VERSION 5.8 ;
BUSBITCHARS "[]" ;
DIVIDERCHAR "/" ;
UNITS
    DATABASE MICRONS 1000 ;
END UNITS

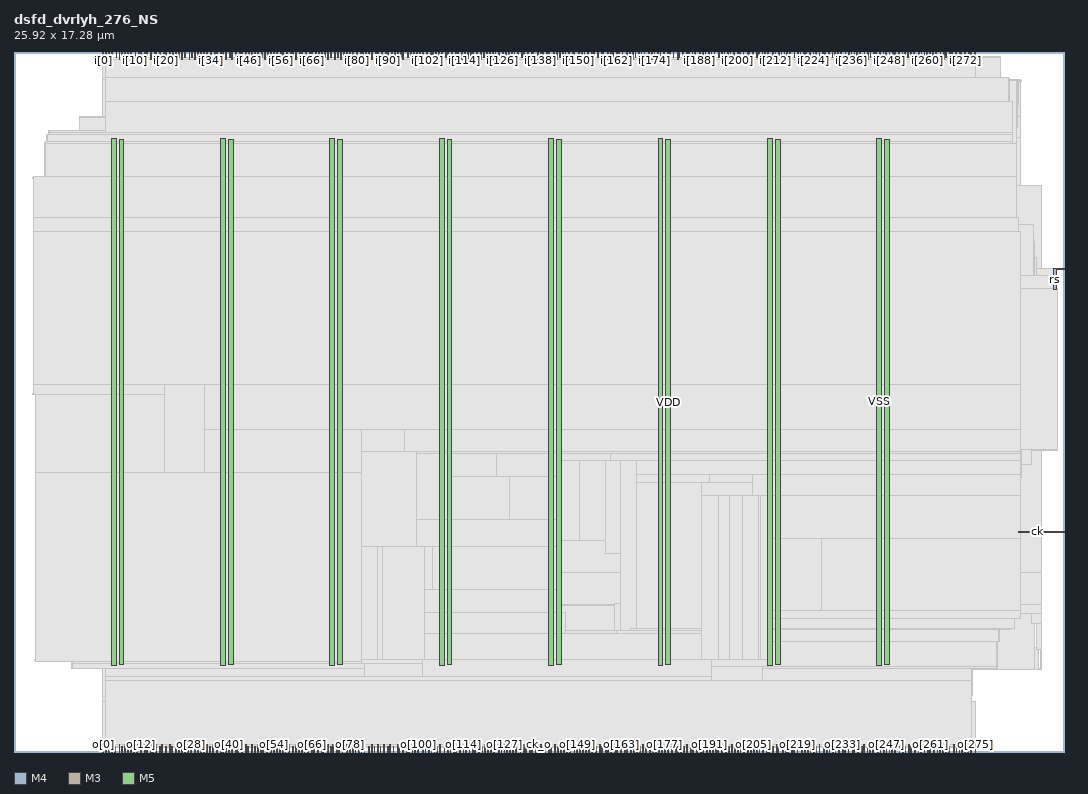
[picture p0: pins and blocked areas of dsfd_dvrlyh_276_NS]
MACRO dsfd_dvrlyh_276_NS
  FOREIGN dsfd_dvrlyh_276_NS 0 0 ;
  CLASS BLOCK ;
  SIZE 25.92 BY 17.28 ;
  PIN ck
    DIRECTION INPUT ;
    USE SIGNAL ;
    PORT
      LAYER M4 ;
        RECT  25.728 5.424 25.92 5.448 ;
    END
    PORT
      LAYER M4 ;
        RECT  24.803 5.424 25.74 5.448 ;
    END
  END ck
  PIN ck_o
    DIRECTION OUTPUT ;
    USE SIGNAL ;
    PORT
      LAYER M3 ;
        RECT  12.96 0 12.978 0.144 ;
    END
  END ck_o
  PIN i[0]
    DIRECTION INPUT ;
    USE SIGNAL ;
    PORT
      LAYER M3 ;
        RECT  2.196 17.136 2.214 17.28 ;
    END
  END i[0]
  PIN i[100]
    DIRECTION INPUT ;
    USE SIGNAL ;
    PORT
      LAYER M3 ;
        RECT  10.008 17.136 10.026 17.28 ;
    END
  END i[100]
  PIN i[101]
    DIRECTION INPUT ;
    USE SIGNAL ;
    PORT
      LAYER M5 ;
        RECT  10.08 17.088 10.104 17.28 ;
    END
  END i[101]
  PIN i[102]
    DIRECTION INPUT ;
    USE SIGNAL ;
    PORT
      LAYER M3 ;
        RECT  10.188 17.136 10.206 17.28 ;
    END
  END i[102]
  PIN i[103]
    DIRECTION INPUT ;
    USE SIGNAL ;
    PORT
      LAYER M5 ;
        RECT  10.272 17.088 10.296 17.28 ;
    END
  END i[103]
  PIN i[104]
    DIRECTION INPUT ;
    USE SIGNAL ;
    PORT
      LAYER M3 ;
        RECT  10.332 17.136 10.35 17.28 ;
    END
  END i[104]
  PIN i[105]
    DIRECTION INPUT ;
    USE SIGNAL ;
    PORT
      LAYER M5 ;
        RECT  10.416 17.088 10.44 17.28 ;
    END
  END i[105]
  PIN i[106]
    DIRECTION INPUT ;
    USE SIGNAL ;
    PORT
      LAYER M3 ;
        RECT  10.476 17.136 10.494 17.28 ;
    END
  END i[106]
  PIN i[107]
    DIRECTION INPUT ;
    USE SIGNAL ;
    PORT
      LAYER M5 ;
        RECT  10.56 17.088 10.584 17.28 ;
    END
  END i[107]
  PIN i[108]
    DIRECTION INPUT ;
    USE SIGNAL ;
    PORT
      LAYER M3 ;
        RECT  10.656 17.136 10.674 17.28 ;
    END
  END i[108]
  PIN i[109]
    DIRECTION INPUT ;
    USE SIGNAL ;
    PORT
      LAYER M5 ;
        RECT  10.704 17.088 10.728 17.28 ;
    END
  END i[109]
  PIN i[10]
    DIRECTION INPUT ;
    USE SIGNAL ;
    PORT
      LAYER M3 ;
        RECT  2.988 17.136 3.006 17.28 ;
    END
  END i[10]
  PIN i[110]
    DIRECTION INPUT ;
    USE SIGNAL ;
    PORT
      LAYER M3 ;
        RECT  10.8 17.136 10.818 17.28 ;
    END
  END i[110]
  PIN i[111]
    DIRECTION INPUT ;
    USE SIGNAL ;
    PORT
      LAYER M5 ;
        RECT  10.896 17.088 10.92 17.28 ;
    END
  END i[111]
  PIN i[112]
    DIRECTION INPUT ;
    USE SIGNAL ;
    PORT
      LAYER M3 ;
        RECT  10.944 17.136 10.962 17.28 ;
    END
  END i[112]
  PIN i[113]
    DIRECTION INPUT ;
    USE SIGNAL ;
    PORT
      LAYER M5 ;
        RECT  11.04 17.088 11.064 17.28 ;
    END
  END i[113]
  PIN i[114]
    DIRECTION INPUT ;
    USE SIGNAL ;
    PORT
      LAYER M3 ;
        RECT  11.124 17.136 11.142 17.28 ;
    END
  END i[114]
  PIN i[115]
    DIRECTION INPUT ;
    USE SIGNAL ;
    PORT
      LAYER M5 ;
        RECT  11.184 17.088 11.208 17.28 ;
    END
  END i[115]
  PIN i[116]
    DIRECTION INPUT ;
    USE SIGNAL ;
    PORT
      LAYER M3 ;
        RECT  11.268 17.136 11.286 17.28 ;
    END
  END i[116]
  PIN i[117]
    DIRECTION INPUT ;
    USE SIGNAL ;
    PORT
      LAYER M5 ;
        RECT  11.328 17.088 11.352 17.28 ;
    END
  END i[117]
  PIN i[118]
    DIRECTION INPUT ;
    USE SIGNAL ;
    PORT
      LAYER M3 ;
        RECT  11.412 17.136 11.43 17.28 ;
    END
  END i[118]
  PIN i[119]
    DIRECTION INPUT ;
    USE SIGNAL ;
    PORT
      LAYER M5 ;
        RECT  11.52 17.088 11.544 17.28 ;
    END
  END i[119]
  PIN i[11]
    DIRECTION INPUT ;
    USE SIGNAL ;
    PORT
      LAYER M5 ;
        RECT  3.072 17.088 3.096 17.28 ;
    END
  END i[11]
  PIN i[120]
    DIRECTION INPUT ;
    USE SIGNAL ;
    PORT
      LAYER M3 ;
        RECT  11.592 17.136 11.61 17.28 ;
    END
  END i[120]
  PIN i[121]
    DIRECTION INPUT ;
    USE SIGNAL ;
    PORT
      LAYER M5 ;
        RECT  11.664 17.088 11.688 17.28 ;
    END
  END i[121]
  PIN i[122]
    DIRECTION INPUT ;
    USE SIGNAL ;
    PORT
      LAYER M3 ;
        RECT  11.736 17.136 11.754 17.28 ;
    END
  END i[122]
  PIN i[123]
    DIRECTION INPUT ;
    USE SIGNAL ;
    PORT
      LAYER M5 ;
        RECT  11.808 17.088 11.832 17.28 ;
    END
  END i[123]
  PIN i[124]
    DIRECTION INPUT ;
    USE SIGNAL ;
    PORT
      LAYER M3 ;
        RECT  11.88 17.136 11.898 17.28 ;
    END
  END i[124]
  PIN i[125]
    DIRECTION INPUT ;
    USE SIGNAL ;
    PORT
      LAYER M5 ;
        RECT  11.952 17.088 11.976 17.28 ;
    END
  END i[125]
  PIN i[126]
    DIRECTION INPUT ;
    USE SIGNAL ;
    PORT
      LAYER M3 ;
        RECT  12.06 17.136 12.078 17.28 ;
    END
  END i[126]
  PIN i[127]
    DIRECTION INPUT ;
    USE SIGNAL ;
    PORT
      LAYER M5 ;
        RECT  12.144 17.088 12.168 17.28 ;
    END
  END i[127]
  PIN i[128]
    DIRECTION INPUT ;
    USE SIGNAL ;
    PORT
      LAYER M3 ;
        RECT  12.204 17.136 12.222 17.28 ;
    END
  END i[128]
  PIN i[129]
    DIRECTION INPUT ;
    USE SIGNAL ;
    PORT
      LAYER M5 ;
        RECT  12.288 17.088 12.312 17.28 ;
    END
  END i[129]
  PIN i[12]
    DIRECTION INPUT ;
    USE SIGNAL ;
    PORT
      LAYER M3 ;
        RECT  3.132 17.136 3.15 17.28 ;
    END
  END i[12]
  PIN i[130]
    DIRECTION INPUT ;
    USE SIGNAL ;
    PORT
      LAYER M3 ;
        RECT  12.348 17.136 12.366 17.28 ;
    END
  END i[130]
  PIN i[131]
    DIRECTION INPUT ;
    USE SIGNAL ;
    PORT
      LAYER M5 ;
        RECT  12.432 17.088 12.456 17.28 ;
    END
  END i[131]
  PIN i[132]
    DIRECTION INPUT ;
    USE SIGNAL ;
    PORT
      LAYER M3 ;
        RECT  12.528 17.136 12.546 17.28 ;
    END
  END i[132]
  PIN i[133]
    DIRECTION INPUT ;
    USE SIGNAL ;
    PORT
      LAYER M5 ;
        RECT  12.576 17.088 12.6 17.28 ;
    END
  END i[133]
  PIN i[134]
    DIRECTION INPUT ;
    USE SIGNAL ;
    PORT
      LAYER M3 ;
        RECT  12.672 17.136 12.69 17.28 ;
    END
  END i[134]
  PIN i[135]
    DIRECTION INPUT ;
    USE SIGNAL ;
    PORT
      LAYER M5 ;
        RECT  12.768 17.088 12.792 17.28 ;
    END
  END i[135]
  PIN i[136]
    DIRECTION INPUT ;
    USE SIGNAL ;
    PORT
      LAYER M3 ;
        RECT  12.816 17.136 12.834 17.28 ;
    END
  END i[136]
  PIN i[137]
    DIRECTION INPUT ;
    USE SIGNAL ;
    PORT
      LAYER M5 ;
        RECT  12.912 17.088 12.936 17.28 ;
    END
  END i[137]
  PIN i[138]
    DIRECTION INPUT ;
    USE SIGNAL ;
    PORT
      LAYER M3 ;
        RECT  12.996 17.136 13.014 17.28 ;
    END
  END i[138]
  PIN i[139]
    DIRECTION INPUT ;
    USE SIGNAL ;
    PORT
      LAYER M5 ;
        RECT  13.056 17.088 13.08 17.28 ;
    END
  END i[139]
  PIN i[13]
    DIRECTION INPUT ;
    USE SIGNAL ;
    PORT
      LAYER M5 ;
        RECT  3.216 17.088 3.24 17.28 ;
    END
  END i[13]
  PIN i[140]
    DIRECTION INPUT ;
    USE SIGNAL ;
    PORT
      LAYER M3 ;
        RECT  13.14 17.136 13.158 17.28 ;
    END
  END i[140]
  PIN i[141]
    DIRECTION INPUT ;
    USE SIGNAL ;
    PORT
      LAYER M5 ;
        RECT  13.2 17.088 13.224 17.28 ;
    END
  END i[141]
  PIN i[142]
    DIRECTION INPUT ;
    USE SIGNAL ;
    PORT
      LAYER M3 ;
        RECT  13.32 17.136 13.338 17.28 ;
    END
  END i[142]
  PIN i[143]
    DIRECTION INPUT ;
    USE SIGNAL ;
    PORT
      LAYER M5 ;
        RECT  13.392 17.088 13.416 17.28 ;
    END
  END i[143]
  PIN i[144]
    DIRECTION INPUT ;
    USE SIGNAL ;
    PORT
      LAYER M3 ;
        RECT  13.464 17.136 13.482 17.28 ;
    END
  END i[144]
  PIN i[145]
    DIRECTION INPUT ;
    USE SIGNAL ;
    PORT
      LAYER M5 ;
        RECT  13.536 17.088 13.56 17.28 ;
    END
  END i[145]
  PIN i[146]
    DIRECTION INPUT ;
    USE SIGNAL ;
    PORT
      LAYER M3 ;
        RECT  13.608 17.136 13.626 17.28 ;
    END
  END i[146]
  PIN i[147]
    DIRECTION INPUT ;
    USE SIGNAL ;
    PORT
      LAYER M5 ;
        RECT  13.68 17.088 13.704 17.28 ;
    END
  END i[147]
  PIN i[148]
    DIRECTION INPUT ;
    USE SIGNAL ;
    PORT
      LAYER M3 ;
        RECT  13.788 17.136 13.806 17.28 ;
    END
  END i[148]
  PIN i[149]
    DIRECTION INPUT ;
    USE SIGNAL ;
    PORT
      LAYER M5 ;
        RECT  13.824 17.088 13.848 17.28 ;
    END
  END i[149]
  PIN i[14]
    DIRECTION INPUT ;
    USE SIGNAL ;
    PORT
      LAYER M3 ;
        RECT  3.276 17.136 3.294 17.28 ;
    END
  END i[14]
  PIN i[150]
    DIRECTION INPUT ;
    USE SIGNAL ;
    PORT
      LAYER M3 ;
        RECT  13.932 17.136 13.95 17.28 ;
    END
  END i[150]
  PIN i[151]
    DIRECTION INPUT ;
    USE SIGNAL ;
    PORT
      LAYER M5 ;
        RECT  14.016 17.088 14.04 17.28 ;
    END
  END i[151]
  PIN i[152]
    DIRECTION INPUT ;
    USE SIGNAL ;
    PORT
      LAYER M3 ;
        RECT  14.076 17.136 14.094 17.28 ;
    END
  END i[152]
  PIN i[153]
    DIRECTION INPUT ;
    USE SIGNAL ;
    PORT
      LAYER M5 ;
        RECT  14.16 17.088 14.184 17.28 ;
    END
  END i[153]
  PIN i[154]
    DIRECTION INPUT ;
    USE SIGNAL ;
    PORT
      LAYER M3 ;
        RECT  14.256 17.136 14.274 17.28 ;
    END
  END i[154]
  PIN i[155]
    DIRECTION INPUT ;
    USE SIGNAL ;
    PORT
      LAYER M5 ;
        RECT  14.304 17.088 14.328 17.28 ;
    END
  END i[155]
  PIN i[156]
    DIRECTION INPUT ;
    USE SIGNAL ;
    PORT
      LAYER M3 ;
        RECT  14.4 17.136 14.418 17.28 ;
    END
  END i[156]
  PIN i[157]
    DIRECTION INPUT ;
    USE SIGNAL ;
    PORT
      LAYER M5 ;
        RECT  14.496 17.088 14.52 17.28 ;
    END
  END i[157]
  PIN i[158]
    DIRECTION INPUT ;
    USE SIGNAL ;
    PORT
      LAYER M3 ;
        RECT  14.544 17.136 14.562 17.28 ;
    END
  END i[158]
  PIN i[159]
    DIRECTION INPUT ;
    USE SIGNAL ;
    PORT
      LAYER M5 ;
        RECT  14.64 17.088 14.664 17.28 ;
    END
  END i[159]
  PIN i[15]
    DIRECTION INPUT ;
    USE SIGNAL ;
    PORT
      LAYER M5 ;
        RECT  3.36 17.088 3.384 17.28 ;
    END
  END i[15]
  PIN i[160]
    DIRECTION INPUT ;
    USE SIGNAL ;
    PORT
      LAYER M3 ;
        RECT  14.724 17.136 14.742 17.28 ;
    END
  END i[160]
  PIN i[161]
    DIRECTION INPUT ;
    USE SIGNAL ;
    PORT
      LAYER M5 ;
        RECT  14.784 17.088 14.808 17.28 ;
    END
  END i[161]
  PIN i[162]
    DIRECTION INPUT ;
    USE SIGNAL ;
    PORT
      LAYER M3 ;
        RECT  14.868 17.136 14.886 17.28 ;
    END
  END i[162]
  PIN i[163]
    DIRECTION INPUT ;
    USE SIGNAL ;
    PORT
      LAYER M5 ;
        RECT  14.928 17.088 14.952 17.28 ;
    END
  END i[163]
  PIN i[164]
    DIRECTION INPUT ;
    USE SIGNAL ;
    PORT
      LAYER M3 ;
        RECT  15.012 17.136 15.03 17.28 ;
    END
  END i[164]
  PIN i[165]
    DIRECTION INPUT ;
    USE SIGNAL ;
    PORT
      LAYER M5 ;
        RECT  15.12 17.088 15.144 17.28 ;
    END
  END i[165]
  PIN i[166]
    DIRECTION INPUT ;
    USE SIGNAL ;
    PORT
      LAYER M3 ;
        RECT  15.192 17.136 15.21 17.28 ;
    END
  END i[166]
  PIN i[167]
    DIRECTION INPUT ;
    USE SIGNAL ;
    PORT
      LAYER M5 ;
        RECT  15.264 17.088 15.288 17.28 ;
    END
  END i[167]
  PIN i[168]
    DIRECTION INPUT ;
    USE SIGNAL ;
    PORT
      LAYER M3 ;
        RECT  15.336 17.136 15.354 17.28 ;
    END
  END i[168]
  PIN i[169]
    DIRECTION INPUT ;
    USE SIGNAL ;
    PORT
      LAYER M5 ;
        RECT  15.408 17.088 15.432 17.28 ;
    END
  END i[169]
  PIN i[16]
    DIRECTION INPUT ;
    USE SIGNAL ;
    PORT
      LAYER M3 ;
        RECT  3.456 17.136 3.474 17.28 ;
    END
  END i[16]
  PIN i[170]
    DIRECTION INPUT ;
    USE SIGNAL ;
    PORT
      LAYER M3 ;
        RECT  15.48 17.136 15.498 17.28 ;
    END
  END i[170]
  PIN i[171]
    DIRECTION INPUT ;
    USE SIGNAL ;
    PORT
      LAYER M5 ;
        RECT  15.552 17.088 15.576 17.28 ;
    END
  END i[171]
  PIN i[172]
    DIRECTION INPUT ;
    USE SIGNAL ;
    PORT
      LAYER M3 ;
        RECT  15.66 17.136 15.678 17.28 ;
    END
  END i[172]
  PIN i[173]
    DIRECTION INPUT ;
    USE SIGNAL ;
    PORT
      LAYER M5 ;
        RECT  15.744 17.088 15.768 17.28 ;
    END
  END i[173]
  PIN i[174]
    DIRECTION INPUT ;
    USE SIGNAL ;
    PORT
      LAYER M3 ;
        RECT  15.804 17.136 15.822 17.28 ;
    END
  END i[174]
  PIN i[175]
    DIRECTION INPUT ;
    USE SIGNAL ;
    PORT
      LAYER M5 ;
        RECT  15.888 17.088 15.912 17.28 ;
    END
  END i[175]
  PIN i[176]
    DIRECTION INPUT ;
    USE SIGNAL ;
    PORT
      LAYER M3 ;
        RECT  15.948 17.136 15.966 17.28 ;
    END
  END i[176]
  PIN i[177]
    DIRECTION INPUT ;
    USE SIGNAL ;
    PORT
      LAYER M5 ;
        RECT  16.032 17.088 16.056 17.28 ;
    END
  END i[177]
  PIN i[178]
    DIRECTION INPUT ;
    USE SIGNAL ;
    PORT
      LAYER M3 ;
        RECT  16.128 17.136 16.146 17.28 ;
    END
  END i[178]
  PIN i[179]
    DIRECTION INPUT ;
    USE SIGNAL ;
    PORT
      LAYER M5 ;
        RECT  16.176 17.088 16.2 17.28 ;
    END
  END i[179]
  PIN i[17]
    DIRECTION INPUT ;
    USE SIGNAL ;
    PORT
      LAYER M5 ;
        RECT  3.504 17.088 3.528 17.28 ;
    END
  END i[17]
  PIN i[180]
    DIRECTION INPUT ;
    USE SIGNAL ;
    PORT
      LAYER M3 ;
        RECT  16.272 17.136 16.29 17.28 ;
    END
  END i[180]
  PIN i[181]
    DIRECTION INPUT ;
    USE SIGNAL ;
    PORT
      LAYER M5 ;
        RECT  16.368 17.088 16.392 17.28 ;
    END
  END i[181]
  PIN i[182]
    DIRECTION INPUT ;
    USE SIGNAL ;
    PORT
      LAYER M3 ;
        RECT  16.416 17.136 16.434 17.28 ;
    END
  END i[182]
  PIN i[183]
    DIRECTION INPUT ;
    USE SIGNAL ;
    PORT
      LAYER M5 ;
        RECT  16.512 17.088 16.536 17.28 ;
    END
  END i[183]
  PIN i[184]
    DIRECTION INPUT ;
    USE SIGNAL ;
    PORT
      LAYER M3 ;
        RECT  16.596 17.136 16.614 17.28 ;
    END
  END i[184]
  PIN i[185]
    DIRECTION INPUT ;
    USE SIGNAL ;
    PORT
      LAYER M5 ;
        RECT  16.656 17.088 16.68 17.28 ;
    END
  END i[185]
  PIN i[186]
    DIRECTION INPUT ;
    USE SIGNAL ;
    PORT
      LAYER M3 ;
        RECT  16.74 17.136 16.758 17.28 ;
    END
  END i[186]
  PIN i[187]
    DIRECTION INPUT ;
    USE SIGNAL ;
    PORT
      LAYER M5 ;
        RECT  16.8 17.088 16.824 17.28 ;
    END
  END i[187]
  PIN i[188]
    DIRECTION INPUT ;
    USE SIGNAL ;
    PORT
      LAYER M3 ;
        RECT  16.92 17.136 16.938 17.28 ;
    END
  END i[188]
  PIN i[189]
    DIRECTION INPUT ;
    USE SIGNAL ;
    PORT
      LAYER M5 ;
        RECT  16.992 17.088 17.016 17.28 ;
    END
  END i[189]
  PIN i[18]
    DIRECTION INPUT ;
    USE SIGNAL ;
    PORT
      LAYER M3 ;
        RECT  3.6 17.136 3.618 17.28 ;
    END
  END i[18]
  PIN i[190]
    DIRECTION INPUT ;
    USE SIGNAL ;
    PORT
      LAYER M3 ;
        RECT  17.064 17.136 17.082 17.28 ;
    END
  END i[190]
  PIN i[191]
    DIRECTION INPUT ;
    USE SIGNAL ;
    PORT
      LAYER M5 ;
        RECT  17.136 17.088 17.16 17.28 ;
    END
  END i[191]
  PIN i[192]
    DIRECTION INPUT ;
    USE SIGNAL ;
    PORT
      LAYER M3 ;
        RECT  17.208 17.136 17.226 17.28 ;
    END
  END i[192]
  PIN i[193]
    DIRECTION INPUT ;
    USE SIGNAL ;
    PORT
      LAYER M5 ;
        RECT  17.28 17.088 17.304 17.28 ;
    END
  END i[193]
  PIN i[194]
    DIRECTION INPUT ;
    USE SIGNAL ;
    PORT
      LAYER M3 ;
        RECT  17.388 17.136 17.406 17.28 ;
    END
  END i[194]
  PIN i[195]
    DIRECTION INPUT ;
    USE SIGNAL ;
    PORT
      LAYER M5 ;
        RECT  17.472 17.088 17.496 17.28 ;
    END
  END i[195]
  PIN i[196]
    DIRECTION INPUT ;
    USE SIGNAL ;
    PORT
      LAYER M3 ;
        RECT  17.532 17.136 17.55 17.28 ;
    END
  END i[196]
  PIN i[197]
    DIRECTION INPUT ;
    USE SIGNAL ;
    PORT
      LAYER M5 ;
        RECT  17.616 17.088 17.64 17.28 ;
    END
  END i[197]
  PIN i[198]
    DIRECTION INPUT ;
    USE SIGNAL ;
    PORT
      LAYER M3 ;
        RECT  17.676 17.136 17.694 17.28 ;
    END
  END i[198]
  PIN i[199]
    DIRECTION INPUT ;
    USE SIGNAL ;
    PORT
      LAYER M5 ;
        RECT  17.76 17.088 17.784 17.28 ;
    END
  END i[199]
  PIN i[19]
    DIRECTION INPUT ;
    USE SIGNAL ;
    PORT
      LAYER M5 ;
        RECT  3.696 17.088 3.72 17.28 ;
    END
  END i[19]
  PIN i[1]
    DIRECTION INPUT ;
    USE SIGNAL ;
    PORT
      LAYER M5 ;
        RECT  2.256 17.088 2.28 17.28 ;
    END
  END i[1]
  PIN i[200]
    DIRECTION INPUT ;
    USE SIGNAL ;
    PORT
      LAYER M3 ;
        RECT  17.856 17.136 17.874 17.28 ;
    END
  END i[200]
  PIN i[201]
    DIRECTION INPUT ;
    USE SIGNAL ;
    PORT
      LAYER M5 ;
        RECT  17.904 17.088 17.928 17.28 ;
    END
  END i[201]
  PIN i[202]
    DIRECTION INPUT ;
    USE SIGNAL ;
    PORT
      LAYER M3 ;
        RECT  18 17.136 18.018 17.28 ;
    END
  END i[202]
  PIN i[203]
    DIRECTION INPUT ;
    USE SIGNAL ;
    PORT
      LAYER M5 ;
        RECT  18.096 17.088 18.12 17.28 ;
    END
  END i[203]
  PIN i[204]
    DIRECTION INPUT ;
    USE SIGNAL ;
    PORT
      LAYER M3 ;
        RECT  18.144 17.136 18.162 17.28 ;
    END
  END i[204]
  PIN i[205]
    DIRECTION INPUT ;
    USE SIGNAL ;
    PORT
      LAYER M5 ;
        RECT  18.24 17.088 18.264 17.28 ;
    END
  END i[205]
  PIN i[206]
    DIRECTION INPUT ;
    USE SIGNAL ;
    PORT
      LAYER M3 ;
        RECT  18.324 17.136 18.342 17.28 ;
    END
  END i[206]
  PIN i[207]
    DIRECTION INPUT ;
    USE SIGNAL ;
    PORT
      LAYER M5 ;
        RECT  18.384 17.088 18.408 17.28 ;
    END
  END i[207]
  PIN i[208]
    DIRECTION INPUT ;
    USE SIGNAL ;
    PORT
      LAYER M3 ;
        RECT  18.468 17.136 18.486 17.28 ;
    END
  END i[208]
  PIN i[209]
    DIRECTION INPUT ;
    USE SIGNAL ;
    PORT
      LAYER M5 ;
        RECT  18.528 17.088 18.552 17.28 ;
    END
  END i[209]
  PIN i[20]
    DIRECTION INPUT ;
    USE SIGNAL ;
    PORT
      LAYER M3 ;
        RECT  3.744 17.136 3.762 17.28 ;
    END
  END i[20]
  PIN i[210]
    DIRECTION INPUT ;
    USE SIGNAL ;
    PORT
      LAYER M3 ;
        RECT  18.612 17.136 18.63 17.28 ;
    END
  END i[210]
  PIN i[211]
    DIRECTION INPUT ;
    USE SIGNAL ;
    PORT
      LAYER M5 ;
        RECT  18.72 17.088 18.744 17.28 ;
    END
  END i[211]
  PIN i[212]
    DIRECTION INPUT ;
    USE SIGNAL ;
    PORT
      LAYER M3 ;
        RECT  18.792 17.136 18.81 17.28 ;
    END
  END i[212]
  PIN i[213]
    DIRECTION INPUT ;
    USE SIGNAL ;
    PORT
      LAYER M5 ;
        RECT  18.864 17.088 18.888 17.28 ;
    END
  END i[213]
  PIN i[214]
    DIRECTION INPUT ;
    USE SIGNAL ;
    PORT
      LAYER M3 ;
        RECT  18.936 17.136 18.954 17.28 ;
    END
  END i[214]
  PIN i[215]
    DIRECTION INPUT ;
    USE SIGNAL ;
    PORT
      LAYER M5 ;
        RECT  19.008 17.088 19.032 17.28 ;
    END
  END i[215]
  PIN i[216]
    DIRECTION INPUT ;
    USE SIGNAL ;
    PORT
      LAYER M3 ;
        RECT  19.08 17.136 19.098 17.28 ;
    END
  END i[216]
  PIN i[217]
    DIRECTION INPUT ;
    USE SIGNAL ;
    PORT
      LAYER M5 ;
        RECT  19.152 17.088 19.176 17.28 ;
    END
  END i[217]
  PIN i[218]
    DIRECTION INPUT ;
    USE SIGNAL ;
    PORT
      LAYER M3 ;
        RECT  19.26 17.136 19.278 17.28 ;
    END
  END i[218]
  PIN i[219]
    DIRECTION INPUT ;
    USE SIGNAL ;
    PORT
      LAYER M5 ;
        RECT  19.344 17.088 19.368 17.28 ;
    END
  END i[219]
  PIN i[21]
    DIRECTION INPUT ;
    USE SIGNAL ;
    PORT
      LAYER M5 ;
        RECT  3.84 17.088 3.864 17.28 ;
    END
  END i[21]
  PIN i[220]
    DIRECTION INPUT ;
    USE SIGNAL ;
    PORT
      LAYER M3 ;
        RECT  19.404 17.136 19.422 17.28 ;
    END
  END i[220]
  PIN i[221]
    DIRECTION INPUT ;
    USE SIGNAL ;
    PORT
      LAYER M5 ;
        RECT  19.488 17.088 19.512 17.28 ;
    END
  END i[221]
  PIN i[222]
    DIRECTION INPUT ;
    USE SIGNAL ;
    PORT
      LAYER M3 ;
        RECT  19.548 17.136 19.566 17.28 ;
    END
  END i[222]
  PIN i[223]
    DIRECTION INPUT ;
    USE SIGNAL ;
    PORT
      LAYER M5 ;
        RECT  19.632 17.088 19.656 17.28 ;
    END
  END i[223]
  PIN i[224]
    DIRECTION INPUT ;
    USE SIGNAL ;
    PORT
      LAYER M3 ;
        RECT  19.728 17.136 19.746 17.28 ;
    END
  END i[224]
  PIN i[225]
    DIRECTION INPUT ;
    USE SIGNAL ;
    PORT
      LAYER M5 ;
        RECT  19.776 17.088 19.8 17.28 ;
    END
  END i[225]
  PIN i[226]
    DIRECTION INPUT ;
    USE SIGNAL ;
    PORT
      LAYER M3 ;
        RECT  19.872 17.136 19.89 17.28 ;
    END
  END i[226]
  PIN i[227]
    DIRECTION INPUT ;
    USE SIGNAL ;
    PORT
      LAYER M5 ;
        RECT  19.968 17.088 19.992 17.28 ;
    END
  END i[227]
  PIN i[228]
    DIRECTION INPUT ;
    USE SIGNAL ;
    PORT
      LAYER M3 ;
        RECT  20.016 17.136 20.034 17.28 ;
    END
  END i[228]
  PIN i[229]
    DIRECTION INPUT ;
    USE SIGNAL ;
    PORT
      LAYER M5 ;
        RECT  20.112 17.088 20.136 17.28 ;
    END
  END i[229]
  PIN i[22]
    DIRECTION INPUT ;
    USE SIGNAL ;
    PORT
      LAYER M3 ;
        RECT  3.924 17.136 3.942 17.28 ;
    END
  END i[22]
  PIN i[230]
    DIRECTION INPUT ;
    USE SIGNAL ;
    PORT
      LAYER M3 ;
        RECT  20.196 17.136 20.214 17.28 ;
    END
  END i[230]
  PIN i[231]
    DIRECTION INPUT ;
    USE SIGNAL ;
    PORT
      LAYER M5 ;
        RECT  20.256 17.088 20.28 17.28 ;
    END
  END i[231]
  PIN i[232]
    DIRECTION INPUT ;
    USE SIGNAL ;
    PORT
      LAYER M3 ;
        RECT  20.34 17.136 20.358 17.28 ;
    END
  END i[232]
  PIN i[233]
    DIRECTION INPUT ;
    USE SIGNAL ;
    PORT
      LAYER M5 ;
        RECT  20.4 17.088 20.424 17.28 ;
    END
  END i[233]
  PIN i[234]
    DIRECTION INPUT ;
    USE SIGNAL ;
    PORT
      LAYER M3 ;
        RECT  20.52 17.136 20.538 17.28 ;
    END
  END i[234]
  PIN i[235]
    DIRECTION INPUT ;
    USE SIGNAL ;
    PORT
      LAYER M5 ;
        RECT  20.592 17.088 20.616 17.28 ;
    END
  END i[235]
  PIN i[236]
    DIRECTION INPUT ;
    USE SIGNAL ;
    PORT
      LAYER M3 ;
        RECT  20.664 17.136 20.682 17.28 ;
    END
  END i[236]
  PIN i[237]
    DIRECTION INPUT ;
    USE SIGNAL ;
    PORT
      LAYER M5 ;
        RECT  20.736 17.088 20.76 17.28 ;
    END
  END i[237]
  PIN i[238]
    DIRECTION INPUT ;
    USE SIGNAL ;
    PORT
      LAYER M3 ;
        RECT  20.808 17.136 20.826 17.28 ;
    END
  END i[238]
  PIN i[239]
    DIRECTION INPUT ;
    USE SIGNAL ;
    PORT
      LAYER M5 ;
        RECT  20.88 17.088 20.904 17.28 ;
    END
  END i[239]
  PIN i[23]
    DIRECTION INPUT ;
    USE SIGNAL ;
    PORT
      LAYER M5 ;
        RECT  3.984 17.088 4.008 17.28 ;
    END
  END i[23]
  PIN i[240]
    DIRECTION INPUT ;
    USE SIGNAL ;
    PORT
      LAYER M3 ;
        RECT  20.988 17.136 21.006 17.28 ;
    END
  END i[240]
  PIN i[241]
    DIRECTION INPUT ;
    USE SIGNAL ;
    PORT
      LAYER M5 ;
        RECT  21.072 17.088 21.096 17.28 ;
    END
  END i[241]
  PIN i[242]
    DIRECTION INPUT ;
    USE SIGNAL ;
    PORT
      LAYER M3 ;
        RECT  21.132 17.136 21.15 17.28 ;
    END
  END i[242]
  PIN i[243]
    DIRECTION INPUT ;
    USE SIGNAL ;
    PORT
      LAYER M5 ;
        RECT  21.216 17.088 21.24 17.28 ;
    END
  END i[243]
  PIN i[244]
    DIRECTION INPUT ;
    USE SIGNAL ;
    PORT
      LAYER M3 ;
        RECT  21.276 17.136 21.294 17.28 ;
    END
  END i[244]
  PIN i[245]
    DIRECTION INPUT ;
    USE SIGNAL ;
    PORT
      LAYER M5 ;
        RECT  21.36 17.088 21.384 17.28 ;
    END
  END i[245]
  PIN i[246]
    DIRECTION INPUT ;
    USE SIGNAL ;
    PORT
      LAYER M3 ;
        RECT  21.456 17.136 21.474 17.28 ;
    END
  END i[246]
  PIN i[247]
    DIRECTION INPUT ;
    USE SIGNAL ;
    PORT
      LAYER M5 ;
        RECT  21.504 17.088 21.528 17.28 ;
    END
  END i[247]
  PIN i[248]
    DIRECTION INPUT ;
    USE SIGNAL ;
    PORT
      LAYER M3 ;
        RECT  21.6 17.136 21.618 17.28 ;
    END
  END i[248]
  PIN i[249]
    DIRECTION INPUT ;
    USE SIGNAL ;
    PORT
      LAYER M5 ;
        RECT  21.696 17.088 21.72 17.28 ;
    END
  END i[249]
  PIN i[24]
    DIRECTION INPUT ;
    USE SIGNAL ;
    PORT
      LAYER M3 ;
        RECT  4.068 17.136 4.086 17.28 ;
    END
  END i[24]
  PIN i[250]
    DIRECTION INPUT ;
    USE SIGNAL ;
    PORT
      LAYER M3 ;
        RECT  21.744 17.136 21.762 17.28 ;
    END
  END i[250]
  PIN i[251]
    DIRECTION INPUT ;
    USE SIGNAL ;
    PORT
      LAYER M5 ;
        RECT  21.84 17.088 21.864 17.28 ;
    END
  END i[251]
  PIN i[252]
    DIRECTION INPUT ;
    USE SIGNAL ;
    PORT
      LAYER M3 ;
        RECT  21.924 17.136 21.942 17.28 ;
    END
  END i[252]
  PIN i[253]
    DIRECTION INPUT ;
    USE SIGNAL ;
    PORT
      LAYER M5 ;
        RECT  21.984 17.088 22.008 17.28 ;
    END
  END i[253]
  PIN i[254]
    DIRECTION INPUT ;
    USE SIGNAL ;
    PORT
      LAYER M3 ;
        RECT  22.068 17.136 22.086 17.28 ;
    END
  END i[254]
  PIN i[255]
    DIRECTION INPUT ;
    USE SIGNAL ;
    PORT
      LAYER M5 ;
        RECT  22.128 17.088 22.152 17.28 ;
    END
  END i[255]
  PIN i[256]
    DIRECTION INPUT ;
    USE SIGNAL ;
    PORT
      LAYER M3 ;
        RECT  22.212 17.136 22.23 17.28 ;
    END
  END i[256]
  PIN i[257]
    DIRECTION INPUT ;
    USE SIGNAL ;
    PORT
      LAYER M5 ;
        RECT  22.32 17.088 22.344 17.28 ;
    END
  END i[257]
  PIN i[258]
    DIRECTION INPUT ;
    USE SIGNAL ;
    PORT
      LAYER M3 ;
        RECT  22.392 17.136 22.41 17.28 ;
    END
  END i[258]
  PIN i[259]
    DIRECTION INPUT ;
    USE SIGNAL ;
    PORT
      LAYER M5 ;
        RECT  22.464 17.088 22.488 17.28 ;
    END
  END i[259]
  PIN i[25]
    DIRECTION INPUT ;
    USE SIGNAL ;
    PORT
      LAYER M5 ;
        RECT  4.128 17.088 4.152 17.28 ;
    END
  END i[25]
  PIN i[260]
    DIRECTION INPUT ;
    USE SIGNAL ;
    PORT
      LAYER M3 ;
        RECT  22.536 17.136 22.554 17.28 ;
    END
  END i[260]
  PIN i[261]
    DIRECTION INPUT ;
    USE SIGNAL ;
    PORT
      LAYER M5 ;
        RECT  22.608 17.088 22.632 17.28 ;
    END
  END i[261]
  PIN i[262]
    DIRECTION INPUT ;
    USE SIGNAL ;
    PORT
      LAYER M3 ;
        RECT  22.68 17.136 22.698 17.28 ;
    END
  END i[262]
  PIN i[263]
    DIRECTION INPUT ;
    USE SIGNAL ;
    PORT
      LAYER M5 ;
        RECT  22.752 17.088 22.776 17.28 ;
    END
  END i[263]
  PIN i[264]
    DIRECTION INPUT ;
    USE SIGNAL ;
    PORT
      LAYER M3 ;
        RECT  22.86 17.136 22.878 17.28 ;
    END
  END i[264]
  PIN i[265]
    DIRECTION INPUT ;
    USE SIGNAL ;
    PORT
      LAYER M5 ;
        RECT  22.944 17.088 22.968 17.28 ;
    END
  END i[265]
  PIN i[266]
    DIRECTION INPUT ;
    USE SIGNAL ;
    PORT
      LAYER M3 ;
        RECT  23.004 17.136 23.022 17.28 ;
    END
  END i[266]
  PIN i[267]
    DIRECTION INPUT ;
    USE SIGNAL ;
    PORT
      LAYER M5 ;
        RECT  23.088 17.088 23.112 17.28 ;
    END
  END i[267]
  PIN i[268]
    DIRECTION INPUT ;
    USE SIGNAL ;
    PORT
      LAYER M3 ;
        RECT  23.148 17.136 23.166 17.28 ;
    END
  END i[268]
  PIN i[269]
    DIRECTION INPUT ;
    USE SIGNAL ;
    PORT
      LAYER M5 ;
        RECT  23.232 17.088 23.256 17.28 ;
    END
  END i[269]
  PIN i[26]
    DIRECTION INPUT ;
    USE SIGNAL ;
    PORT
      LAYER M3 ;
        RECT  4.212 17.136 4.23 17.28 ;
    END
  END i[26]
  PIN i[270]
    DIRECTION INPUT ;
    USE SIGNAL ;
    PORT
      LAYER M3 ;
        RECT  23.328 17.136 23.346 17.28 ;
    END
  END i[270]
  PIN i[271]
    DIRECTION INPUT ;
    USE SIGNAL ;
    PORT
      LAYER M5 ;
        RECT  23.376 17.088 23.4 17.28 ;
    END
  END i[271]
  PIN i[272]
    DIRECTION INPUT ;
    USE SIGNAL ;
    PORT
      LAYER M3 ;
        RECT  23.472 17.136 23.49 17.28 ;
    END
  END i[272]
  PIN i[273]
    DIRECTION INPUT ;
    USE SIGNAL ;
    PORT
      LAYER M5 ;
        RECT  23.568 17.088 23.592 17.28 ;
    END
  END i[273]
  PIN i[274]
    DIRECTION INPUT ;
    USE SIGNAL ;
    PORT
      LAYER M3 ;
        RECT  23.616 17.136 23.634 17.28 ;
    END
  END i[274]
  PIN i[275]
    DIRECTION INPUT ;
    USE SIGNAL ;
    PORT
      LAYER M5 ;
        RECT  23.712 17.088 23.736 17.28 ;
    END
  END i[275]
  PIN i[27]
    DIRECTION INPUT ;
    USE SIGNAL ;
    PORT
      LAYER M5 ;
        RECT  4.32 17.088 4.344 17.28 ;
    END
  END i[27]
  PIN i[28]
    DIRECTION INPUT ;
    USE SIGNAL ;
    PORT
      LAYER M3 ;
        RECT  4.392 17.136 4.41 17.28 ;
    END
  END i[28]
  PIN i[29]
    DIRECTION INPUT ;
    USE SIGNAL ;
    PORT
      LAYER M5 ;
        RECT  4.464 17.088 4.488 17.28 ;
    END
  END i[29]
  PIN i[2]
    DIRECTION INPUT ;
    USE SIGNAL ;
    PORT
      LAYER M3 ;
        RECT  2.34 17.136 2.358 17.28 ;
    END
  END i[2]
  PIN i[30]
    DIRECTION INPUT ;
    USE SIGNAL ;
    PORT
      LAYER M3 ;
        RECT  4.536 17.136 4.554 17.28 ;
    END
  END i[30]
  PIN i[31]
    DIRECTION INPUT ;
    USE SIGNAL ;
    PORT
      LAYER M5 ;
        RECT  4.608 17.088 4.632 17.28 ;
    END
  END i[31]
  PIN i[32]
    DIRECTION INPUT ;
    USE SIGNAL ;
    PORT
      LAYER M3 ;
        RECT  4.68 17.136 4.698 17.28 ;
    END
  END i[32]
  PIN i[33]
    DIRECTION INPUT ;
    USE SIGNAL ;
    PORT
      LAYER M5 ;
        RECT  4.752 17.088 4.776 17.28 ;
    END
  END i[33]
  PIN i[34]
    DIRECTION INPUT ;
    USE SIGNAL ;
    PORT
      LAYER M3 ;
        RECT  4.86 17.136 4.878 17.28 ;
    END
  END i[34]
  PIN i[35]
    DIRECTION INPUT ;
    USE SIGNAL ;
    PORT
      LAYER M5 ;
        RECT  4.944 17.088 4.968 17.28 ;
    END
  END i[35]
  PIN i[36]
    DIRECTION INPUT ;
    USE SIGNAL ;
    PORT
      LAYER M3 ;
        RECT  5.004 17.136 5.022 17.28 ;
    END
  END i[36]
  PIN i[37]
    DIRECTION INPUT ;
    USE SIGNAL ;
    PORT
      LAYER M5 ;
        RECT  5.088 17.088 5.112 17.28 ;
    END
  END i[37]
  PIN i[38]
    DIRECTION INPUT ;
    USE SIGNAL ;
    PORT
      LAYER M3 ;
        RECT  5.148 17.136 5.166 17.28 ;
    END
  END i[38]
  PIN i[39]
    DIRECTION INPUT ;
    USE SIGNAL ;
    PORT
      LAYER M5 ;
        RECT  5.232 17.088 5.256 17.28 ;
    END
  END i[39]
  PIN i[3]
    DIRECTION INPUT ;
    USE SIGNAL ;
    PORT
      LAYER M5 ;
        RECT  2.4 17.088 2.424 17.28 ;
    END
  END i[3]
  PIN i[40]
    DIRECTION INPUT ;
    USE SIGNAL ;
    PORT
      LAYER M3 ;
        RECT  5.328 17.136 5.346 17.28 ;
    END
  END i[40]
  PIN i[41]
    DIRECTION INPUT ;
    USE SIGNAL ;
    PORT
      LAYER M5 ;
        RECT  5.376 17.088 5.4 17.28 ;
    END
  END i[41]
  PIN i[42]
    DIRECTION INPUT ;
    USE SIGNAL ;
    PORT
      LAYER M3 ;
        RECT  5.472 17.136 5.49 17.28 ;
    END
  END i[42]
  PIN i[43]
    DIRECTION INPUT ;
    USE SIGNAL ;
    PORT
      LAYER M5 ;
        RECT  5.568 17.088 5.592 17.28 ;
    END
  END i[43]
  PIN i[44]
    DIRECTION INPUT ;
    USE SIGNAL ;
    PORT
      LAYER M3 ;
        RECT  5.616 17.136 5.634 17.28 ;
    END
  END i[44]
  PIN i[45]
    DIRECTION INPUT ;
    USE SIGNAL ;
    PORT
      LAYER M5 ;
        RECT  5.712 17.088 5.736 17.28 ;
    END
  END i[45]
  PIN i[46]
    DIRECTION INPUT ;
    USE SIGNAL ;
    PORT
      LAYER M3 ;
        RECT  5.796 17.136 5.814 17.28 ;
    END
  END i[46]
  PIN i[47]
    DIRECTION INPUT ;
    USE SIGNAL ;
    PORT
      LAYER M5 ;
        RECT  5.856 17.088 5.88 17.28 ;
    END
  END i[47]
  PIN i[48]
    DIRECTION INPUT ;
    USE SIGNAL ;
    PORT
      LAYER M3 ;
        RECT  5.94 17.136 5.958 17.28 ;
    END
  END i[48]
  PIN i[49]
    DIRECTION INPUT ;
    USE SIGNAL ;
    PORT
      LAYER M5 ;
        RECT  6 17.088 6.024 17.28 ;
    END
  END i[49]
  PIN i[4]
    DIRECTION INPUT ;
    USE SIGNAL ;
    PORT
      LAYER M3 ;
        RECT  2.52 17.136 2.538 17.28 ;
    END
  END i[4]
  PIN i[50]
    DIRECTION INPUT ;
    USE SIGNAL ;
    PORT
      LAYER M3 ;
        RECT  6.12 17.136 6.138 17.28 ;
    END
  END i[50]
  PIN i[51]
    DIRECTION INPUT ;
    USE SIGNAL ;
    PORT
      LAYER M5 ;
        RECT  6.192 17.088 6.216 17.28 ;
    END
  END i[51]
  PIN i[52]
    DIRECTION INPUT ;
    USE SIGNAL ;
    PORT
      LAYER M3 ;
        RECT  6.264 17.136 6.282 17.28 ;
    END
  END i[52]
  PIN i[53]
    DIRECTION INPUT ;
    USE SIGNAL ;
    PORT
      LAYER M5 ;
        RECT  6.336 17.088 6.36 17.28 ;
    END
  END i[53]
  PIN i[54]
    DIRECTION INPUT ;
    USE SIGNAL ;
    PORT
      LAYER M3 ;
        RECT  6.408 17.136 6.426 17.28 ;
    END
  END i[54]
  PIN i[55]
    DIRECTION INPUT ;
    USE SIGNAL ;
    PORT
      LAYER M5 ;
        RECT  6.48 17.088 6.504 17.28 ;
    END
  END i[55]
  PIN i[56]
    DIRECTION INPUT ;
    USE SIGNAL ;
    PORT
      LAYER M3 ;
        RECT  6.588 17.136 6.606 17.28 ;
    END
  END i[56]
  PIN i[57]
    DIRECTION INPUT ;
    USE SIGNAL ;
    PORT
      LAYER M5 ;
        RECT  6.624 17.088 6.648 17.28 ;
    END
  END i[57]
  PIN i[58]
    DIRECTION INPUT ;
    USE SIGNAL ;
    PORT
      LAYER M3 ;
        RECT  6.732 17.136 6.75 17.28 ;
    END
  END i[58]
  PIN i[59]
    DIRECTION INPUT ;
    USE SIGNAL ;
    PORT
      LAYER M5 ;
        RECT  6.816 17.088 6.84 17.28 ;
    END
  END i[59]
  PIN i[5]
    DIRECTION INPUT ;
    USE SIGNAL ;
    PORT
      LAYER M5 ;
        RECT  2.592 17.088 2.616 17.28 ;
    END
  END i[5]
  PIN i[60]
    DIRECTION INPUT ;
    USE SIGNAL ;
    PORT
      LAYER M3 ;
        RECT  6.876 17.136 6.894 17.28 ;
    END
  END i[60]
  PIN i[61]
    DIRECTION INPUT ;
    USE SIGNAL ;
    PORT
      LAYER M5 ;
        RECT  6.96 17.088 6.984 17.28 ;
    END
  END i[61]
  PIN i[62]
    DIRECTION INPUT ;
    USE SIGNAL ;
    PORT
      LAYER M3 ;
        RECT  7.056 17.136 7.074 17.28 ;
    END
  END i[62]
  PIN i[63]
    DIRECTION INPUT ;
    USE SIGNAL ;
    PORT
      LAYER M5 ;
        RECT  7.104 17.088 7.128 17.28 ;
    END
  END i[63]
  PIN i[64]
    DIRECTION INPUT ;
    USE SIGNAL ;
    PORT
      LAYER M3 ;
        RECT  7.2 17.136 7.218 17.28 ;
    END
  END i[64]
  PIN i[65]
    DIRECTION INPUT ;
    USE SIGNAL ;
    PORT
      LAYER M5 ;
        RECT  7.296 17.088 7.32 17.28 ;
    END
  END i[65]
  PIN i[66]
    DIRECTION INPUT ;
    USE SIGNAL ;
    PORT
      LAYER M3 ;
        RECT  7.344 17.136 7.362 17.28 ;
    END
  END i[66]
  PIN i[67]
    DIRECTION INPUT ;
    USE SIGNAL ;
    PORT
      LAYER M5 ;
        RECT  7.44 17.088 7.464 17.28 ;
    END
  END i[67]
  PIN i[68]
    DIRECTION INPUT ;
    USE SIGNAL ;
    PORT
      LAYER M3 ;
        RECT  7.524 17.136 7.542 17.28 ;
    END
  END i[68]
  PIN i[69]
    DIRECTION INPUT ;
    USE SIGNAL ;
    PORT
      LAYER M5 ;
        RECT  7.584 17.088 7.608 17.28 ;
    END
  END i[69]
  PIN i[6]
    DIRECTION INPUT ;
    USE SIGNAL ;
    PORT
      LAYER M3 ;
        RECT  2.664 17.136 2.682 17.28 ;
    END
  END i[6]
  PIN i[70]
    DIRECTION INPUT ;
    USE SIGNAL ;
    PORT
      LAYER M3 ;
        RECT  7.668 17.136 7.686 17.28 ;
    END
  END i[70]
  PIN i[71]
    DIRECTION INPUT ;
    USE SIGNAL ;
    PORT
      LAYER M5 ;
        RECT  7.728 17.088 7.752 17.28 ;
    END
  END i[71]
  PIN i[72]
    DIRECTION INPUT ;
    USE SIGNAL ;
    PORT
      LAYER M3 ;
        RECT  7.812 17.136 7.83 17.28 ;
    END
  END i[72]
  PIN i[73]
    DIRECTION INPUT ;
    USE SIGNAL ;
    PORT
      LAYER M5 ;
        RECT  7.92 17.088 7.944 17.28 ;
    END
  END i[73]
  PIN i[74]
    DIRECTION INPUT ;
    USE SIGNAL ;
    PORT
      LAYER M3 ;
        RECT  7.992 17.136 8.01 17.28 ;
    END
  END i[74]
  PIN i[75]
    DIRECTION INPUT ;
    USE SIGNAL ;
    PORT
      LAYER M5 ;
        RECT  8.064 17.088 8.088 17.28 ;
    END
  END i[75]
  PIN i[76]
    DIRECTION INPUT ;
    USE SIGNAL ;
    PORT
      LAYER M3 ;
        RECT  8.136 17.136 8.154 17.28 ;
    END
  END i[76]
  PIN i[77]
    DIRECTION INPUT ;
    USE SIGNAL ;
    PORT
      LAYER M5 ;
        RECT  8.208 17.088 8.232 17.28 ;
    END
  END i[77]
  PIN i[78]
    DIRECTION INPUT ;
    USE SIGNAL ;
    PORT
      LAYER M3 ;
        RECT  8.28 17.136 8.298 17.28 ;
    END
  END i[78]
  PIN i[79]
    DIRECTION INPUT ;
    USE SIGNAL ;
    PORT
      LAYER M5 ;
        RECT  8.352 17.088 8.376 17.28 ;
    END
  END i[79]
  PIN i[7]
    DIRECTION INPUT ;
    USE SIGNAL ;
    PORT
      LAYER M5 ;
        RECT  2.736 17.088 2.76 17.28 ;
    END
  END i[7]
  PIN i[80]
    DIRECTION INPUT ;
    USE SIGNAL ;
    PORT
      LAYER M3 ;
        RECT  8.46 17.136 8.478 17.28 ;
    END
  END i[80]
  PIN i[81]
    DIRECTION INPUT ;
    USE SIGNAL ;
    PORT
      LAYER M5 ;
        RECT  8.544 17.088 8.568 17.28 ;
    END
  END i[81]
  PIN i[82]
    DIRECTION INPUT ;
    USE SIGNAL ;
    PORT
      LAYER M3 ;
        RECT  8.604 17.136 8.622 17.28 ;
    END
  END i[82]
  PIN i[83]
    DIRECTION INPUT ;
    USE SIGNAL ;
    PORT
      LAYER M5 ;
        RECT  8.688 17.088 8.712 17.28 ;
    END
  END i[83]
  PIN i[84]
    DIRECTION INPUT ;
    USE SIGNAL ;
    PORT
      LAYER M3 ;
        RECT  8.748 17.136 8.766 17.28 ;
    END
  END i[84]
  PIN i[85]
    DIRECTION INPUT ;
    USE SIGNAL ;
    PORT
      LAYER M5 ;
        RECT  8.832 17.088 8.856 17.28 ;
    END
  END i[85]
  PIN i[86]
    DIRECTION INPUT ;
    USE SIGNAL ;
    PORT
      LAYER M3 ;
        RECT  8.928 17.136 8.946 17.28 ;
    END
  END i[86]
  PIN i[87]
    DIRECTION INPUT ;
    USE SIGNAL ;
    PORT
      LAYER M5 ;
        RECT  8.976 17.088 9 17.28 ;
    END
  END i[87]
  PIN i[88]
    DIRECTION INPUT ;
    USE SIGNAL ;
    PORT
      LAYER M3 ;
        RECT  9.072 17.136 9.09 17.28 ;
    END
  END i[88]
  PIN i[89]
    DIRECTION INPUT ;
    USE SIGNAL ;
    PORT
      LAYER M5 ;
        RECT  9.168 17.088 9.192 17.28 ;
    END
  END i[89]
  PIN i[8]
    DIRECTION INPUT ;
    USE SIGNAL ;
    PORT
      LAYER M3 ;
        RECT  2.808 17.136 2.826 17.28 ;
    END
  END i[8]
  PIN i[90]
    DIRECTION INPUT ;
    USE SIGNAL ;
    PORT
      LAYER M3 ;
        RECT  9.216 17.136 9.234 17.28 ;
    END
  END i[90]
  PIN i[91]
    DIRECTION INPUT ;
    USE SIGNAL ;
    PORT
      LAYER M5 ;
        RECT  9.312 17.088 9.336 17.28 ;
    END
  END i[91]
  PIN i[92]
    DIRECTION INPUT ;
    USE SIGNAL ;
    PORT
      LAYER M3 ;
        RECT  9.396 17.136 9.414 17.28 ;
    END
  END i[92]
  PIN i[93]
    DIRECTION INPUT ;
    USE SIGNAL ;
    PORT
      LAYER M5 ;
        RECT  9.456 17.088 9.48 17.28 ;
    END
  END i[93]
  PIN i[94]
    DIRECTION INPUT ;
    USE SIGNAL ;
    PORT
      LAYER M3 ;
        RECT  9.54 17.136 9.558 17.28 ;
    END
  END i[94]
  PIN i[95]
    DIRECTION INPUT ;
    USE SIGNAL ;
    PORT
      LAYER M5 ;
        RECT  9.6 17.088 9.624 17.28 ;
    END
  END i[95]
  PIN i[96]
    DIRECTION INPUT ;
    USE SIGNAL ;
    PORT
      LAYER M3 ;
        RECT  9.72 17.136 9.738 17.28 ;
    END
  END i[96]
  PIN i[97]
    DIRECTION INPUT ;
    USE SIGNAL ;
    PORT
      LAYER M5 ;
        RECT  9.792 17.088 9.816 17.28 ;
    END
  END i[97]
  PIN i[98]
    DIRECTION INPUT ;
    USE SIGNAL ;
    PORT
      LAYER M3 ;
        RECT  9.864 17.136 9.882 17.28 ;
    END
  END i[98]
  PIN i[99]
    DIRECTION INPUT ;
    USE SIGNAL ;
    PORT
      LAYER M5 ;
        RECT  9.936 17.088 9.96 17.28 ;
    END
  END i[99]
  PIN i[9]
    DIRECTION INPUT ;
    USE SIGNAL ;
    PORT
      LAYER M5 ;
        RECT  2.88 17.088 2.904 17.28 ;
    END
  END i[9]
  PIN o[0]
    DIRECTION OUTPUT ;
    USE SIGNAL ;
    PORT
      LAYER M3 ;
        RECT  2.196 0 2.214 0.144 ;
    END
  END o[0]
  PIN o[100]
    DIRECTION OUTPUT ;
    USE SIGNAL ;
    PORT
      LAYER M3 ;
        RECT  9.972 0 9.99 0.144 ;
    END
  END o[100]
  PIN o[101]
    DIRECTION OUTPUT ;
    USE SIGNAL ;
    PORT
      LAYER M5 ;
        RECT  10.08 0 10.104 0.192 ;
    END
  END o[101]
  PIN o[102]
    DIRECTION OUTPUT ;
    USE SIGNAL ;
    PORT
      LAYER M3 ;
        RECT  10.152 0 10.17 0.144 ;
    END
  END o[102]
  PIN o[103]
    DIRECTION OUTPUT ;
    USE SIGNAL ;
    PORT
      LAYER M5 ;
        RECT  10.224 0 10.248 0.192 ;
    END
  END o[103]
  PIN o[104]
    DIRECTION OUTPUT ;
    USE SIGNAL ;
    PORT
      LAYER M3 ;
        RECT  10.296 0 10.314 0.144 ;
    END
  END o[104]
  PIN o[105]
    DIRECTION OUTPUT ;
    USE SIGNAL ;
    PORT
      LAYER M5 ;
        RECT  10.368 0 10.392 0.192 ;
    END
  END o[105]
  PIN o[106]
    DIRECTION OUTPUT ;
    USE SIGNAL ;
    PORT
      LAYER M3 ;
        RECT  10.44 0 10.458 0.144 ;
    END
  END o[106]
  PIN o[107]
    DIRECTION OUTPUT ;
    USE SIGNAL ;
    PORT
      LAYER M5 ;
        RECT  10.512 0 10.536 0.192 ;
    END
  END o[107]
  PIN o[108]
    DIRECTION OUTPUT ;
    USE SIGNAL ;
    PORT
      LAYER M3 ;
        RECT  10.62 0 10.638 0.144 ;
    END
  END o[108]
  PIN o[109]
    DIRECTION OUTPUT ;
    USE SIGNAL ;
    PORT
      LAYER M5 ;
        RECT  10.704 0 10.728 0.192 ;
    END
  END o[109]
  PIN o[10]
    DIRECTION OUTPUT ;
    USE SIGNAL ;
    PORT
      LAYER M3 ;
        RECT  2.952 0 2.97 0.144 ;
    END
  END o[10]
  PIN o[110]
    DIRECTION OUTPUT ;
    USE SIGNAL ;
    PORT
      LAYER M3 ;
        RECT  10.764 0 10.782 0.144 ;
    END
  END o[110]
  PIN o[111]
    DIRECTION OUTPUT ;
    USE SIGNAL ;
    PORT
      LAYER M5 ;
        RECT  10.848 0 10.872 0.192 ;
    END
  END o[111]
  PIN o[112]
    DIRECTION OUTPUT ;
    USE SIGNAL ;
    PORT
      LAYER M3 ;
        RECT  10.908 0 10.926 0.144 ;
    END
  END o[112]
  PIN o[113]
    DIRECTION OUTPUT ;
    USE SIGNAL ;
    PORT
      LAYER M5 ;
        RECT  10.992 0 11.016 0.192 ;
    END
  END o[113]
  PIN o[114]
    DIRECTION OUTPUT ;
    USE SIGNAL ;
    PORT
      LAYER M3 ;
        RECT  11.088 0 11.106 0.144 ;
    END
  END o[114]
  PIN o[115]
    DIRECTION OUTPUT ;
    USE SIGNAL ;
    PORT
      LAYER M5 ;
        RECT  11.136 0 11.16 0.192 ;
    END
  END o[115]
  PIN o[116]
    DIRECTION OUTPUT ;
    USE SIGNAL ;
    PORT
      LAYER M3 ;
        RECT  11.232 0 11.25 0.144 ;
    END
  END o[116]
  PIN o[117]
    DIRECTION OUTPUT ;
    USE SIGNAL ;
    PORT
      LAYER M5 ;
        RECT  11.328 0 11.352 0.192 ;
    END
  END o[117]
  PIN o[118]
    DIRECTION OUTPUT ;
    USE SIGNAL ;
    PORT
      LAYER M3 ;
        RECT  11.376 0 11.394 0.144 ;
    END
  END o[118]
  PIN o[119]
    DIRECTION OUTPUT ;
    USE SIGNAL ;
    PORT
      LAYER M5 ;
        RECT  11.472 0 11.496 0.192 ;
    END
  END o[119]
  PIN o[11]
    DIRECTION OUTPUT ;
    USE SIGNAL ;
    PORT
      LAYER M5 ;
        RECT  3.024 0 3.048 0.192 ;
    END
  END o[11]
  PIN o[120]
    DIRECTION OUTPUT ;
    USE SIGNAL ;
    PORT
      LAYER M3 ;
        RECT  11.556 0 11.574 0.144 ;
    END
  END o[120]
  PIN o[121]
    DIRECTION OUTPUT ;
    USE SIGNAL ;
    PORT
      LAYER M5 ;
        RECT  11.616 0 11.64 0.192 ;
    END
  END o[121]
  PIN o[122]
    DIRECTION OUTPUT ;
    USE SIGNAL ;
    PORT
      LAYER M3 ;
        RECT  11.7 0 11.718 0.144 ;
    END
  END o[122]
  PIN o[123]
    DIRECTION OUTPUT ;
    USE SIGNAL ;
    PORT
      LAYER M5 ;
        RECT  11.76 0 11.784 0.192 ;
    END
  END o[123]
  PIN o[124]
    DIRECTION OUTPUT ;
    USE SIGNAL ;
    PORT
      LAYER M3 ;
        RECT  11.844 0 11.862 0.144 ;
    END
  END o[124]
  PIN o[125]
    DIRECTION OUTPUT ;
    USE SIGNAL ;
    PORT
      LAYER M5 ;
        RECT  11.952 0 11.976 0.192 ;
    END
  END o[125]
  PIN o[126]
    DIRECTION OUTPUT ;
    USE SIGNAL ;
    PORT
      LAYER M3 ;
        RECT  12.024 0 12.042 0.144 ;
    END
  END o[126]
  PIN o[127]
    DIRECTION OUTPUT ;
    USE SIGNAL ;
    PORT
      LAYER M5 ;
        RECT  12.096 0 12.12 0.192 ;
    END
  END o[127]
  PIN o[128]
    DIRECTION OUTPUT ;
    USE SIGNAL ;
    PORT
      LAYER M3 ;
        RECT  12.168 0 12.186 0.144 ;
    END
  END o[128]
  PIN o[129]
    DIRECTION OUTPUT ;
    USE SIGNAL ;
    PORT
      LAYER M5 ;
        RECT  12.24 0 12.264 0.192 ;
    END
  END o[129]
  PIN o[12]
    DIRECTION OUTPUT ;
    USE SIGNAL ;
    PORT
      LAYER M3 ;
        RECT  3.132 0 3.15 0.144 ;
    END
  END o[12]
  PIN o[130]
    DIRECTION OUTPUT ;
    USE SIGNAL ;
    PORT
      LAYER M3 ;
        RECT  12.312 0 12.33 0.144 ;
    END
  END o[130]
  PIN o[131]
    DIRECTION OUTPUT ;
    USE SIGNAL ;
    PORT
      LAYER M5 ;
        RECT  12.384 0 12.408 0.192 ;
    END
  END o[131]
  PIN o[132]
    DIRECTION OUTPUT ;
    USE SIGNAL ;
    PORT
      LAYER M3 ;
        RECT  12.492 0 12.51 0.144 ;
    END
  END o[132]
  PIN o[133]
    DIRECTION OUTPUT ;
    USE SIGNAL ;
    PORT
      LAYER M5 ;
        RECT  12.576 0 12.6 0.192 ;
    END
  END o[133]
  PIN o[134]
    DIRECTION OUTPUT ;
    USE SIGNAL ;
    PORT
      LAYER M3 ;
        RECT  12.636 0 12.654 0.144 ;
    END
  END o[134]
  PIN o[135]
    DIRECTION OUTPUT ;
    USE SIGNAL ;
    PORT
      LAYER M5 ;
        RECT  12.72 0 12.744 0.192 ;
    END
  END o[135]
  PIN o[136]
    DIRECTION OUTPUT ;
    USE SIGNAL ;
    PORT
      LAYER M3 ;
        RECT  12.78 0 12.798 0.144 ;
    END
  END o[136]
  PIN o[137]
    DIRECTION OUTPUT ;
    USE SIGNAL ;
    PORT
      LAYER M5 ;
        RECT  12.864 0 12.888 0.192 ;
    END
  END o[137]
  PIN o[138]
    DIRECTION OUTPUT ;
    USE SIGNAL ;
    PORT
      LAYER M5 ;
        RECT  13.008 0 13.032 0.192 ;
    END
  END o[138]
  PIN o[139]
    DIRECTION OUTPUT ;
    USE SIGNAL ;
    PORT
      LAYER M3 ;
        RECT  13.104 0 13.122 0.144 ;
    END
  END o[139]
  PIN o[13]
    DIRECTION OUTPUT ;
    USE SIGNAL ;
    PORT
      LAYER M5 ;
        RECT  3.216 0 3.24 0.192 ;
    END
  END o[13]
  PIN o[140]
    DIRECTION OUTPUT ;
    USE SIGNAL ;
    PORT
      LAYER M5 ;
        RECT  13.2 0 13.224 0.192 ;
    END
  END o[140]
  PIN o[141]
    DIRECTION OUTPUT ;
    USE SIGNAL ;
    PORT
      LAYER M3 ;
        RECT  13.248 0 13.266 0.144 ;
    END
  END o[141]
  PIN o[142]
    DIRECTION OUTPUT ;
    USE SIGNAL ;
    PORT
      LAYER M5 ;
        RECT  13.344 0 13.368 0.192 ;
    END
  END o[142]
  PIN o[143]
    DIRECTION OUTPUT ;
    USE SIGNAL ;
    PORT
      LAYER M3 ;
        RECT  13.428 0 13.446 0.144 ;
    END
  END o[143]
  PIN o[144]
    DIRECTION OUTPUT ;
    USE SIGNAL ;
    PORT
      LAYER M5 ;
        RECT  13.488 0 13.512 0.192 ;
    END
  END o[144]
  PIN o[145]
    DIRECTION OUTPUT ;
    USE SIGNAL ;
    PORT
      LAYER M3 ;
        RECT  13.572 0 13.59 0.144 ;
    END
  END o[145]
  PIN o[146]
    DIRECTION OUTPUT ;
    USE SIGNAL ;
    PORT
      LAYER M5 ;
        RECT  13.632 0 13.656 0.192 ;
    END
  END o[146]
  PIN o[147]
    DIRECTION OUTPUT ;
    USE SIGNAL ;
    PORT
      LAYER M3 ;
        RECT  13.716 0 13.734 0.144 ;
    END
  END o[147]
  PIN o[148]
    DIRECTION OUTPUT ;
    USE SIGNAL ;
    PORT
      LAYER M5 ;
        RECT  13.824 0 13.848 0.192 ;
    END
  END o[148]
  PIN o[149]
    DIRECTION OUTPUT ;
    USE SIGNAL ;
    PORT
      LAYER M3 ;
        RECT  13.896 0 13.914 0.144 ;
    END
  END o[149]
  PIN o[14]
    DIRECTION OUTPUT ;
    USE SIGNAL ;
    PORT
      LAYER M3 ;
        RECT  3.276 0 3.294 0.144 ;
    END
  END o[14]
  PIN o[150]
    DIRECTION OUTPUT ;
    USE SIGNAL ;
    PORT
      LAYER M5 ;
        RECT  13.968 0 13.992 0.192 ;
    END
  END o[150]
  PIN o[151]
    DIRECTION OUTPUT ;
    USE SIGNAL ;
    PORT
      LAYER M3 ;
        RECT  14.04 0 14.058 0.144 ;
    END
  END o[151]
  PIN o[152]
    DIRECTION OUTPUT ;
    USE SIGNAL ;
    PORT
      LAYER M5 ;
        RECT  14.112 0 14.136 0.192 ;
    END
  END o[152]
  PIN o[153]
    DIRECTION OUTPUT ;
    USE SIGNAL ;
    PORT
      LAYER M3 ;
        RECT  14.184 0 14.202 0.144 ;
    END
  END o[153]
  PIN o[154]
    DIRECTION OUTPUT ;
    USE SIGNAL ;
    PORT
      LAYER M5 ;
        RECT  14.256 0 14.28 0.192 ;
    END
  END o[154]
  PIN o[155]
    DIRECTION OUTPUT ;
    USE SIGNAL ;
    PORT
      LAYER M3 ;
        RECT  14.364 0 14.382 0.144 ;
    END
  END o[155]
  PIN o[156]
    DIRECTION OUTPUT ;
    USE SIGNAL ;
    PORT
      LAYER M5 ;
        RECT  14.448 0 14.472 0.192 ;
    END
  END o[156]
  PIN o[157]
    DIRECTION OUTPUT ;
    USE SIGNAL ;
    PORT
      LAYER M3 ;
        RECT  14.508 0 14.526 0.144 ;
    END
  END o[157]
  PIN o[158]
    DIRECTION OUTPUT ;
    USE SIGNAL ;
    PORT
      LAYER M5 ;
        RECT  14.592 0 14.616 0.192 ;
    END
  END o[158]
  PIN o[159]
    DIRECTION OUTPUT ;
    USE SIGNAL ;
    PORT
      LAYER M3 ;
        RECT  14.652 0 14.67 0.144 ;
    END
  END o[159]
  PIN o[15]
    DIRECTION OUTPUT ;
    USE SIGNAL ;
    PORT
      LAYER M5 ;
        RECT  3.36 0 3.384 0.192 ;
    END
  END o[15]
  PIN o[160]
    DIRECTION OUTPUT ;
    USE SIGNAL ;
    PORT
      LAYER M5 ;
        RECT  14.736 0 14.76 0.192 ;
    END
  END o[160]
  PIN o[161]
    DIRECTION OUTPUT ;
    USE SIGNAL ;
    PORT
      LAYER M3 ;
        RECT  14.832 0 14.85 0.144 ;
    END
  END o[161]
  PIN o[162]
    DIRECTION OUTPUT ;
    USE SIGNAL ;
    PORT
      LAYER M5 ;
        RECT  14.88 0 14.904 0.192 ;
    END
  END o[162]
  PIN o[163]
    DIRECTION OUTPUT ;
    USE SIGNAL ;
    PORT
      LAYER M3 ;
        RECT  14.976 0 14.994 0.144 ;
    END
  END o[163]
  PIN o[164]
    DIRECTION OUTPUT ;
    USE SIGNAL ;
    PORT
      LAYER M5 ;
        RECT  15.072 0 15.096 0.192 ;
    END
  END o[164]
  PIN o[165]
    DIRECTION OUTPUT ;
    USE SIGNAL ;
    PORT
      LAYER M3 ;
        RECT  15.12 0 15.138 0.144 ;
    END
  END o[165]
  PIN o[166]
    DIRECTION OUTPUT ;
    USE SIGNAL ;
    PORT
      LAYER M5 ;
        RECT  15.216 0 15.24 0.192 ;
    END
  END o[166]
  PIN o[167]
    DIRECTION OUTPUT ;
    USE SIGNAL ;
    PORT
      LAYER M3 ;
        RECT  15.3 0 15.318 0.144 ;
    END
  END o[167]
  PIN o[168]
    DIRECTION OUTPUT ;
    USE SIGNAL ;
    PORT
      LAYER M5 ;
        RECT  15.36 0 15.384 0.192 ;
    END
  END o[168]
  PIN o[169]
    DIRECTION OUTPUT ;
    USE SIGNAL ;
    PORT
      LAYER M3 ;
        RECT  15.444 0 15.462 0.144 ;
    END
  END o[169]
  PIN o[16]
    DIRECTION OUTPUT ;
    USE SIGNAL ;
    PORT
      LAYER M3 ;
        RECT  3.42 0 3.438 0.144 ;
    END
  END o[16]
  PIN o[170]
    DIRECTION OUTPUT ;
    USE SIGNAL ;
    PORT
      LAYER M5 ;
        RECT  15.504 0 15.528 0.192 ;
    END
  END o[170]
  PIN o[171]
    DIRECTION OUTPUT ;
    USE SIGNAL ;
    PORT
      LAYER M3 ;
        RECT  15.588 0 15.606 0.144 ;
    END
  END o[171]
  PIN o[172]
    DIRECTION OUTPUT ;
    USE SIGNAL ;
    PORT
      LAYER M5 ;
        RECT  15.696 0 15.72 0.192 ;
    END
  END o[172]
  PIN o[173]
    DIRECTION OUTPUT ;
    USE SIGNAL ;
    PORT
      LAYER M3 ;
        RECT  15.768 0 15.786 0.144 ;
    END
  END o[173]
  PIN o[174]
    DIRECTION OUTPUT ;
    USE SIGNAL ;
    PORT
      LAYER M5 ;
        RECT  15.84 0 15.864 0.192 ;
    END
  END o[174]
  PIN o[175]
    DIRECTION OUTPUT ;
    USE SIGNAL ;
    PORT
      LAYER M3 ;
        RECT  15.912 0 15.93 0.144 ;
    END
  END o[175]
  PIN o[176]
    DIRECTION OUTPUT ;
    USE SIGNAL ;
    PORT
      LAYER M5 ;
        RECT  15.984 0 16.008 0.192 ;
    END
  END o[176]
  PIN o[177]
    DIRECTION OUTPUT ;
    USE SIGNAL ;
    PORT
      LAYER M3 ;
        RECT  16.056 0 16.074 0.144 ;
    END
  END o[177]
  PIN o[178]
    DIRECTION OUTPUT ;
    USE SIGNAL ;
    PORT
      LAYER M5 ;
        RECT  16.128 0 16.152 0.192 ;
    END
  END o[178]
  PIN o[179]
    DIRECTION OUTPUT ;
    USE SIGNAL ;
    PORT
      LAYER M3 ;
        RECT  16.236 0 16.254 0.144 ;
    END
  END o[179]
  PIN o[17]
    DIRECTION OUTPUT ;
    USE SIGNAL ;
    PORT
      LAYER M5 ;
        RECT  3.504 0 3.528 0.192 ;
    END
  END o[17]
  PIN o[180]
    DIRECTION OUTPUT ;
    USE SIGNAL ;
    PORT
      LAYER M5 ;
        RECT  16.32 0 16.344 0.192 ;
    END
  END o[180]
  PIN o[181]
    DIRECTION OUTPUT ;
    USE SIGNAL ;
    PORT
      LAYER M3 ;
        RECT  16.38 0 16.398 0.144 ;
    END
  END o[181]
  PIN o[182]
    DIRECTION OUTPUT ;
    USE SIGNAL ;
    PORT
      LAYER M5 ;
        RECT  16.464 0 16.488 0.192 ;
    END
  END o[182]
  PIN o[183]
    DIRECTION OUTPUT ;
    USE SIGNAL ;
    PORT
      LAYER M3 ;
        RECT  16.524 0 16.542 0.144 ;
    END
  END o[183]
  PIN o[184]
    DIRECTION OUTPUT ;
    USE SIGNAL ;
    PORT
      LAYER M5 ;
        RECT  16.608 0 16.632 0.192 ;
    END
  END o[184]
  PIN o[185]
    DIRECTION OUTPUT ;
    USE SIGNAL ;
    PORT
      LAYER M3 ;
        RECT  16.704 0 16.722 0.144 ;
    END
  END o[185]
  PIN o[186]
    DIRECTION OUTPUT ;
    USE SIGNAL ;
    PORT
      LAYER M5 ;
        RECT  16.752 0 16.776 0.192 ;
    END
  END o[186]
  PIN o[187]
    DIRECTION OUTPUT ;
    USE SIGNAL ;
    PORT
      LAYER M3 ;
        RECT  16.848 0 16.866 0.144 ;
    END
  END o[187]
  PIN o[188]
    DIRECTION OUTPUT ;
    USE SIGNAL ;
    PORT
      LAYER M5 ;
        RECT  16.944 0 16.968 0.192 ;
    END
  END o[188]
  PIN o[189]
    DIRECTION OUTPUT ;
    USE SIGNAL ;
    PORT
      LAYER M3 ;
        RECT  16.992 0 17.01 0.144 ;
    END
  END o[189]
  PIN o[18]
    DIRECTION OUTPUT ;
    USE SIGNAL ;
    PORT
      LAYER M3 ;
        RECT  3.6 0 3.618 0.144 ;
    END
  END o[18]
  PIN o[190]
    DIRECTION OUTPUT ;
    USE SIGNAL ;
    PORT
      LAYER M5 ;
        RECT  17.088 0 17.112 0.192 ;
    END
  END o[190]
  PIN o[191]
    DIRECTION OUTPUT ;
    USE SIGNAL ;
    PORT
      LAYER M3 ;
        RECT  17.172 0 17.19 0.144 ;
    END
  END o[191]
  PIN o[192]
    DIRECTION OUTPUT ;
    USE SIGNAL ;
    PORT
      LAYER M5 ;
        RECT  17.232 0 17.256 0.192 ;
    END
  END o[192]
  PIN o[193]
    DIRECTION OUTPUT ;
    USE SIGNAL ;
    PORT
      LAYER M3 ;
        RECT  17.316 0 17.334 0.144 ;
    END
  END o[193]
  PIN o[194]
    DIRECTION OUTPUT ;
    USE SIGNAL ;
    PORT
      LAYER M5 ;
        RECT  17.376 0 17.4 0.192 ;
    END
  END o[194]
  PIN o[195]
    DIRECTION OUTPUT ;
    USE SIGNAL ;
    PORT
      LAYER M3 ;
        RECT  17.46 0 17.478 0.144 ;
    END
  END o[195]
  PIN o[196]
    DIRECTION OUTPUT ;
    USE SIGNAL ;
    PORT
      LAYER M5 ;
        RECT  17.568 0 17.592 0.192 ;
    END
  END o[196]
  PIN o[197]
    DIRECTION OUTPUT ;
    USE SIGNAL ;
    PORT
      LAYER M3 ;
        RECT  17.64 0 17.658 0.144 ;
    END
  END o[197]
  PIN o[198]
    DIRECTION OUTPUT ;
    USE SIGNAL ;
    PORT
      LAYER M5 ;
        RECT  17.712 0 17.736 0.192 ;
    END
  END o[198]
  PIN o[199]
    DIRECTION OUTPUT ;
    USE SIGNAL ;
    PORT
      LAYER M3 ;
        RECT  17.784 0 17.802 0.144 ;
    END
  END o[199]
  PIN o[19]
    DIRECTION OUTPUT ;
    USE SIGNAL ;
    PORT
      LAYER M5 ;
        RECT  3.648 0 3.672 0.192 ;
    END
  END o[19]
  PIN o[1]
    DIRECTION OUTPUT ;
    USE SIGNAL ;
    PORT
      LAYER M5 ;
        RECT  2.256 0 2.28 0.192 ;
    END
  END o[1]
  PIN o[200]
    DIRECTION OUTPUT ;
    USE SIGNAL ;
    PORT
      LAYER M5 ;
        RECT  17.856 0 17.88 0.192 ;
    END
  END o[200]
  PIN o[201]
    DIRECTION OUTPUT ;
    USE SIGNAL ;
    PORT
      LAYER M3 ;
        RECT  17.928 0 17.946 0.144 ;
    END
  END o[201]
  PIN o[202]
    DIRECTION OUTPUT ;
    USE SIGNAL ;
    PORT
      LAYER M5 ;
        RECT  18 0 18.024 0.192 ;
    END
  END o[202]
  PIN o[203]
    DIRECTION OUTPUT ;
    USE SIGNAL ;
    PORT
      LAYER M3 ;
        RECT  18.108 0 18.126 0.144 ;
    END
  END o[203]
  PIN o[204]
    DIRECTION OUTPUT ;
    USE SIGNAL ;
    PORT
      LAYER M5 ;
        RECT  18.192 0 18.216 0.192 ;
    END
  END o[204]
  PIN o[205]
    DIRECTION OUTPUT ;
    USE SIGNAL ;
    PORT
      LAYER M3 ;
        RECT  18.252 0 18.27 0.144 ;
    END
  END o[205]
  PIN o[206]
    DIRECTION OUTPUT ;
    USE SIGNAL ;
    PORT
      LAYER M5 ;
        RECT  18.336 0 18.36 0.192 ;
    END
  END o[206]
  PIN o[207]
    DIRECTION OUTPUT ;
    USE SIGNAL ;
    PORT
      LAYER M3 ;
        RECT  18.396 0 18.414 0.144 ;
    END
  END o[207]
  PIN o[208]
    DIRECTION OUTPUT ;
    USE SIGNAL ;
    PORT
      LAYER M5 ;
        RECT  18.48 0 18.504 0.192 ;
    END
  END o[208]
  PIN o[209]
    DIRECTION OUTPUT ;
    USE SIGNAL ;
    PORT
      LAYER M3 ;
        RECT  18.576 0 18.594 0.144 ;
    END
  END o[209]
  PIN o[20]
    DIRECTION OUTPUT ;
    USE SIGNAL ;
    PORT
      LAYER M3 ;
        RECT  3.744 0 3.762 0.144 ;
    END
  END o[20]
  PIN o[210]
    DIRECTION OUTPUT ;
    USE SIGNAL ;
    PORT
      LAYER M5 ;
        RECT  18.624 0 18.648 0.192 ;
    END
  END o[210]
  PIN o[211]
    DIRECTION OUTPUT ;
    USE SIGNAL ;
    PORT
      LAYER M3 ;
        RECT  18.72 0 18.738 0.144 ;
    END
  END o[211]
  PIN o[212]
    DIRECTION OUTPUT ;
    USE SIGNAL ;
    PORT
      LAYER M5 ;
        RECT  18.816 0 18.84 0.192 ;
    END
  END o[212]
  PIN o[213]
    DIRECTION OUTPUT ;
    USE SIGNAL ;
    PORT
      LAYER M3 ;
        RECT  18.864 0 18.882 0.144 ;
    END
  END o[213]
  PIN o[214]
    DIRECTION OUTPUT ;
    USE SIGNAL ;
    PORT
      LAYER M5 ;
        RECT  18.96 0 18.984 0.192 ;
    END
  END o[214]
  PIN o[215]
    DIRECTION OUTPUT ;
    USE SIGNAL ;
    PORT
      LAYER M3 ;
        RECT  19.044 0 19.062 0.144 ;
    END
  END o[215]
  PIN o[216]
    DIRECTION OUTPUT ;
    USE SIGNAL ;
    PORT
      LAYER M5 ;
        RECT  19.104 0 19.128 0.192 ;
    END
  END o[216]
  PIN o[217]
    DIRECTION OUTPUT ;
    USE SIGNAL ;
    PORT
      LAYER M3 ;
        RECT  19.188 0 19.206 0.144 ;
    END
  END o[217]
  PIN o[218]
    DIRECTION OUTPUT ;
    USE SIGNAL ;
    PORT
      LAYER M5 ;
        RECT  19.248 0 19.272 0.192 ;
    END
  END o[218]
  PIN o[219]
    DIRECTION OUTPUT ;
    USE SIGNAL ;
    PORT
      LAYER M3 ;
        RECT  19.332 0 19.35 0.144 ;
    END
  END o[219]
  PIN o[21]
    DIRECTION OUTPUT ;
    USE SIGNAL ;
    PORT
      LAYER M5 ;
        RECT  3.84 0 3.864 0.192 ;
    END
  END o[21]
  PIN o[220]
    DIRECTION OUTPUT ;
    USE SIGNAL ;
    PORT
      LAYER M5 ;
        RECT  19.44 0 19.464 0.192 ;
    END
  END o[220]
  PIN o[221]
    DIRECTION OUTPUT ;
    USE SIGNAL ;
    PORT
      LAYER M3 ;
        RECT  19.512 0 19.53 0.144 ;
    END
  END o[221]
  PIN o[222]
    DIRECTION OUTPUT ;
    USE SIGNAL ;
    PORT
      LAYER M5 ;
        RECT  19.584 0 19.608 0.192 ;
    END
  END o[222]
  PIN o[223]
    DIRECTION OUTPUT ;
    USE SIGNAL ;
    PORT
      LAYER M3 ;
        RECT  19.656 0 19.674 0.144 ;
    END
  END o[223]
  PIN o[224]
    DIRECTION OUTPUT ;
    USE SIGNAL ;
    PORT
      LAYER M5 ;
        RECT  19.728 0 19.752 0.192 ;
    END
  END o[224]
  PIN o[225]
    DIRECTION OUTPUT ;
    USE SIGNAL ;
    PORT
      LAYER M3 ;
        RECT  19.8 0 19.818 0.144 ;
    END
  END o[225]
  PIN o[226]
    DIRECTION OUTPUT ;
    USE SIGNAL ;
    PORT
      LAYER M5 ;
        RECT  19.872 0 19.896 0.192 ;
    END
  END o[226]
  PIN o[227]
    DIRECTION OUTPUT ;
    USE SIGNAL ;
    PORT
      LAYER M3 ;
        RECT  19.98 0 19.998 0.144 ;
    END
  END o[227]
  PIN o[228]
    DIRECTION OUTPUT ;
    USE SIGNAL ;
    PORT
      LAYER M5 ;
        RECT  20.064 0 20.088 0.192 ;
    END
  END o[228]
  PIN o[229]
    DIRECTION OUTPUT ;
    USE SIGNAL ;
    PORT
      LAYER M3 ;
        RECT  20.124 0 20.142 0.144 ;
    END
  END o[229]
  PIN o[22]
    DIRECTION OUTPUT ;
    USE SIGNAL ;
    PORT
      LAYER M3 ;
        RECT  3.888 0 3.906 0.144 ;
    END
  END o[22]
  PIN o[230]
    DIRECTION OUTPUT ;
    USE SIGNAL ;
    PORT
      LAYER M5 ;
        RECT  20.208 0 20.232 0.192 ;
    END
  END o[230]
  PIN o[231]
    DIRECTION OUTPUT ;
    USE SIGNAL ;
    PORT
      LAYER M3 ;
        RECT  20.268 0 20.286 0.144 ;
    END
  END o[231]
  PIN o[232]
    DIRECTION OUTPUT ;
    USE SIGNAL ;
    PORT
      LAYER M5 ;
        RECT  20.352 0 20.376 0.192 ;
    END
  END o[232]
  PIN o[233]
    DIRECTION OUTPUT ;
    USE SIGNAL ;
    PORT
      LAYER M3 ;
        RECT  20.448 0 20.466 0.144 ;
    END
  END o[233]
  PIN o[234]
    DIRECTION OUTPUT ;
    USE SIGNAL ;
    PORT
      LAYER M5 ;
        RECT  20.496 0 20.52 0.192 ;
    END
  END o[234]
  PIN o[235]
    DIRECTION OUTPUT ;
    USE SIGNAL ;
    PORT
      LAYER M3 ;
        RECT  20.592 0 20.61 0.144 ;
    END
  END o[235]
  PIN o[236]
    DIRECTION OUTPUT ;
    USE SIGNAL ;
    PORT
      LAYER M5 ;
        RECT  20.688 0 20.712 0.192 ;
    END
  END o[236]
  PIN o[237]
    DIRECTION OUTPUT ;
    USE SIGNAL ;
    PORT
      LAYER M3 ;
        RECT  20.736 0 20.754 0.144 ;
    END
  END o[237]
  PIN o[238]
    DIRECTION OUTPUT ;
    USE SIGNAL ;
    PORT
      LAYER M5 ;
        RECT  20.832 0 20.856 0.192 ;
    END
  END o[238]
  PIN o[239]
    DIRECTION OUTPUT ;
    USE SIGNAL ;
    PORT
      LAYER M3 ;
        RECT  20.916 0 20.934 0.144 ;
    END
  END o[239]
  PIN o[23]
    DIRECTION OUTPUT ;
    USE SIGNAL ;
    PORT
      LAYER M5 ;
        RECT  3.984 0 4.008 0.192 ;
    END
  END o[23]
  PIN o[240]
    DIRECTION OUTPUT ;
    USE SIGNAL ;
    PORT
      LAYER M5 ;
        RECT  20.976 0 21 0.192 ;
    END
  END o[240]
  PIN o[241]
    DIRECTION OUTPUT ;
    USE SIGNAL ;
    PORT
      LAYER M3 ;
        RECT  21.06 0 21.078 0.144 ;
    END
  END o[241]
  PIN o[242]
    DIRECTION OUTPUT ;
    USE SIGNAL ;
    PORT
      LAYER M5 ;
        RECT  21.12 0 21.144 0.192 ;
    END
  END o[242]
  PIN o[243]
    DIRECTION OUTPUT ;
    USE SIGNAL ;
    PORT
      LAYER M3 ;
        RECT  21.204 0 21.222 0.144 ;
    END
  END o[243]
  PIN o[244]
    DIRECTION OUTPUT ;
    USE SIGNAL ;
    PORT
      LAYER M5 ;
        RECT  21.312 0 21.336 0.192 ;
    END
  END o[244]
  PIN o[245]
    DIRECTION OUTPUT ;
    USE SIGNAL ;
    PORT
      LAYER M3 ;
        RECT  21.384 0 21.402 0.144 ;
    END
  END o[245]
  PIN o[246]
    DIRECTION OUTPUT ;
    USE SIGNAL ;
    PORT
      LAYER M5 ;
        RECT  21.456 0 21.48 0.192 ;
    END
  END o[246]
  PIN o[247]
    DIRECTION OUTPUT ;
    USE SIGNAL ;
    PORT
      LAYER M3 ;
        RECT  21.528 0 21.546 0.144 ;
    END
  END o[247]
  PIN o[248]
    DIRECTION OUTPUT ;
    USE SIGNAL ;
    PORT
      LAYER M5 ;
        RECT  21.6 0 21.624 0.192 ;
    END
  END o[248]
  PIN o[249]
    DIRECTION OUTPUT ;
    USE SIGNAL ;
    PORT
      LAYER M3 ;
        RECT  21.672 0 21.69 0.144 ;
    END
  END o[249]
  PIN o[24]
    DIRECTION OUTPUT ;
    USE SIGNAL ;
    PORT
      LAYER M3 ;
        RECT  4.068 0 4.086 0.144 ;
    END
  END o[24]
  PIN o[250]
    DIRECTION OUTPUT ;
    USE SIGNAL ;
    PORT
      LAYER M5 ;
        RECT  21.744 0 21.768 0.192 ;
    END
  END o[250]
  PIN o[251]
    DIRECTION OUTPUT ;
    USE SIGNAL ;
    PORT
      LAYER M3 ;
        RECT  21.852 0 21.87 0.144 ;
    END
  END o[251]
  PIN o[252]
    DIRECTION OUTPUT ;
    USE SIGNAL ;
    PORT
      LAYER M5 ;
        RECT  21.936 0 21.96 0.192 ;
    END
  END o[252]
  PIN o[253]
    DIRECTION OUTPUT ;
    USE SIGNAL ;
    PORT
      LAYER M3 ;
        RECT  21.996 0 22.014 0.144 ;
    END
  END o[253]
  PIN o[254]
    DIRECTION OUTPUT ;
    USE SIGNAL ;
    PORT
      LAYER M5 ;
        RECT  22.08 0 22.104 0.192 ;
    END
  END o[254]
  PIN o[255]
    DIRECTION OUTPUT ;
    USE SIGNAL ;
    PORT
      LAYER M3 ;
        RECT  22.14 0 22.158 0.144 ;
    END
  END o[255]
  PIN o[256]
    DIRECTION OUTPUT ;
    USE SIGNAL ;
    PORT
      LAYER M5 ;
        RECT  22.224 0 22.248 0.192 ;
    END
  END o[256]
  PIN o[257]
    DIRECTION OUTPUT ;
    USE SIGNAL ;
    PORT
      LAYER M3 ;
        RECT  22.32 0 22.338 0.144 ;
    END
  END o[257]
  PIN o[258]
    DIRECTION OUTPUT ;
    USE SIGNAL ;
    PORT
      LAYER M5 ;
        RECT  22.368 0 22.392 0.192 ;
    END
  END o[258]
  PIN o[259]
    DIRECTION OUTPUT ;
    USE SIGNAL ;
    PORT
      LAYER M3 ;
        RECT  22.464 0 22.482 0.144 ;
    END
  END o[259]
  PIN o[25]
    DIRECTION OUTPUT ;
    USE SIGNAL ;
    PORT
      LAYER M5 ;
        RECT  4.128 0 4.152 0.192 ;
    END
  END o[25]
  PIN o[260]
    DIRECTION OUTPUT ;
    USE SIGNAL ;
    PORT
      LAYER M5 ;
        RECT  22.56 0 22.584 0.192 ;
    END
  END o[260]
  PIN o[261]
    DIRECTION OUTPUT ;
    USE SIGNAL ;
    PORT
      LAYER M3 ;
        RECT  22.608 0 22.626 0.144 ;
    END
  END o[261]
  PIN o[262]
    DIRECTION OUTPUT ;
    USE SIGNAL ;
    PORT
      LAYER M5 ;
        RECT  22.704 0 22.728 0.192 ;
    END
  END o[262]
  PIN o[263]
    DIRECTION OUTPUT ;
    USE SIGNAL ;
    PORT
      LAYER M3 ;
        RECT  22.788 0 22.806 0.144 ;
    END
  END o[263]
  PIN o[264]
    DIRECTION OUTPUT ;
    USE SIGNAL ;
    PORT
      LAYER M5 ;
        RECT  22.848 0 22.872 0.192 ;
    END
  END o[264]
  PIN o[265]
    DIRECTION OUTPUT ;
    USE SIGNAL ;
    PORT
      LAYER M3 ;
        RECT  22.932 0 22.95 0.144 ;
    END
  END o[265]
  PIN o[266]
    DIRECTION OUTPUT ;
    USE SIGNAL ;
    PORT
      LAYER M5 ;
        RECT  22.992 0 23.016 0.192 ;
    END
  END o[266]
  PIN o[267]
    DIRECTION OUTPUT ;
    USE SIGNAL ;
    PORT
      LAYER M3 ;
        RECT  23.076 0 23.094 0.144 ;
    END
  END o[267]
  PIN o[268]
    DIRECTION OUTPUT ;
    USE SIGNAL ;
    PORT
      LAYER M5 ;
        RECT  23.184 0 23.208 0.192 ;
    END
  END o[268]
  PIN o[269]
    DIRECTION OUTPUT ;
    USE SIGNAL ;
    PORT
      LAYER M3 ;
        RECT  23.256 0 23.274 0.144 ;
    END
  END o[269]
  PIN o[26]
    DIRECTION OUTPUT ;
    USE SIGNAL ;
    PORT
      LAYER M3 ;
        RECT  4.212 0 4.23 0.144 ;
    END
  END o[26]
  PIN o[270]
    DIRECTION OUTPUT ;
    USE SIGNAL ;
    PORT
      LAYER M5 ;
        RECT  23.328 0 23.352 0.192 ;
    END
  END o[270]
  PIN o[271]
    DIRECTION OUTPUT ;
    USE SIGNAL ;
    PORT
      LAYER M3 ;
        RECT  23.4 0 23.418 0.144 ;
    END
  END o[271]
  PIN o[272]
    DIRECTION OUTPUT ;
    USE SIGNAL ;
    PORT
      LAYER M5 ;
        RECT  23.472 0 23.496 0.192 ;
    END
  END o[272]
  PIN o[273]
    DIRECTION OUTPUT ;
    USE SIGNAL ;
    PORT
      LAYER M3 ;
        RECT  23.544 0 23.562 0.144 ;
    END
  END o[273]
  PIN o[274]
    DIRECTION OUTPUT ;
    USE SIGNAL ;
    PORT
      LAYER M5 ;
        RECT  23.616 0 23.64 0.192 ;
    END
  END o[274]
  PIN o[275]
    DIRECTION OUTPUT ;
    USE SIGNAL ;
    PORT
      LAYER M3 ;
        RECT  23.724 0 23.742 0.144 ;
    END
  END o[275]
  PIN o[27]
    DIRECTION OUTPUT ;
    USE SIGNAL ;
    PORT
      LAYER M5 ;
        RECT  4.272 0 4.296 0.192 ;
    END
  END o[27]
  PIN o[28]
    DIRECTION OUTPUT ;
    USE SIGNAL ;
    PORT
      LAYER M3 ;
        RECT  4.356 0 4.374 0.144 ;
    END
  END o[28]
  PIN o[29]
    DIRECTION OUTPUT ;
    USE SIGNAL ;
    PORT
      LAYER M5 ;
        RECT  4.464 0 4.488 0.192 ;
    END
  END o[29]
  PIN o[2]
    DIRECTION OUTPUT ;
    USE SIGNAL ;
    PORT
      LAYER M3 ;
        RECT  2.34 0 2.358 0.144 ;
    END
  END o[2]
  PIN o[30]
    DIRECTION OUTPUT ;
    USE SIGNAL ;
    PORT
      LAYER M3 ;
        RECT  4.536 0 4.554 0.144 ;
    END
  END o[30]
  PIN o[31]
    DIRECTION OUTPUT ;
    USE SIGNAL ;
    PORT
      LAYER M5 ;
        RECT  4.608 0 4.632 0.192 ;
    END
  END o[31]
  PIN o[32]
    DIRECTION OUTPUT ;
    USE SIGNAL ;
    PORT
      LAYER M3 ;
        RECT  4.68 0 4.698 0.144 ;
    END
  END o[32]
  PIN o[33]
    DIRECTION OUTPUT ;
    USE SIGNAL ;
    PORT
      LAYER M5 ;
        RECT  4.752 0 4.776 0.192 ;
    END
  END o[33]
  PIN o[34]
    DIRECTION OUTPUT ;
    USE SIGNAL ;
    PORT
      LAYER M3 ;
        RECT  4.824 0 4.842 0.144 ;
    END
  END o[34]
  PIN o[35]
    DIRECTION OUTPUT ;
    USE SIGNAL ;
    PORT
      LAYER M5 ;
        RECT  4.896 0 4.92 0.192 ;
    END
  END o[35]
  PIN o[36]
    DIRECTION OUTPUT ;
    USE SIGNAL ;
    PORT
      LAYER M3 ;
        RECT  5.004 0 5.022 0.144 ;
    END
  END o[36]
  PIN o[37]
    DIRECTION OUTPUT ;
    USE SIGNAL ;
    PORT
      LAYER M5 ;
        RECT  5.088 0 5.112 0.192 ;
    END
  END o[37]
  PIN o[38]
    DIRECTION OUTPUT ;
    USE SIGNAL ;
    PORT
      LAYER M3 ;
        RECT  5.148 0 5.166 0.144 ;
    END
  END o[38]
  PIN o[39]
    DIRECTION OUTPUT ;
    USE SIGNAL ;
    PORT
      LAYER M5 ;
        RECT  5.232 0 5.256 0.192 ;
    END
  END o[39]
  PIN o[3]
    DIRECTION OUTPUT ;
    USE SIGNAL ;
    PORT
      LAYER M5 ;
        RECT  2.4 0 2.424 0.192 ;
    END
  END o[3]
  PIN o[40]
    DIRECTION OUTPUT ;
    USE SIGNAL ;
    PORT
      LAYER M3 ;
        RECT  5.292 0 5.31 0.144 ;
    END
  END o[40]
  PIN o[41]
    DIRECTION OUTPUT ;
    USE SIGNAL ;
    PORT
      LAYER M5 ;
        RECT  5.376 0 5.4 0.192 ;
    END
  END o[41]
  PIN o[42]
    DIRECTION OUTPUT ;
    USE SIGNAL ;
    PORT
      LAYER M3 ;
        RECT  5.472 0 5.49 0.144 ;
    END
  END o[42]
  PIN o[43]
    DIRECTION OUTPUT ;
    USE SIGNAL ;
    PORT
      LAYER M5 ;
        RECT  5.52 0 5.544 0.192 ;
    END
  END o[43]
  PIN o[44]
    DIRECTION OUTPUT ;
    USE SIGNAL ;
    PORT
      LAYER M3 ;
        RECT  5.616 0 5.634 0.144 ;
    END
  END o[44]
  PIN o[45]
    DIRECTION OUTPUT ;
    USE SIGNAL ;
    PORT
      LAYER M5 ;
        RECT  5.712 0 5.736 0.192 ;
    END
  END o[45]
  PIN o[46]
    DIRECTION OUTPUT ;
    USE SIGNAL ;
    PORT
      LAYER M3 ;
        RECT  5.76 0 5.778 0.144 ;
    END
  END o[46]
  PIN o[47]
    DIRECTION OUTPUT ;
    USE SIGNAL ;
    PORT
      LAYER M5 ;
        RECT  5.856 0 5.88 0.192 ;
    END
  END o[47]
  PIN o[48]
    DIRECTION OUTPUT ;
    USE SIGNAL ;
    PORT
      LAYER M3 ;
        RECT  5.94 0 5.958 0.144 ;
    END
  END o[48]
  PIN o[49]
    DIRECTION OUTPUT ;
    USE SIGNAL ;
    PORT
      LAYER M5 ;
        RECT  6 0 6.024 0.192 ;
    END
  END o[49]
  PIN o[4]
    DIRECTION OUTPUT ;
    USE SIGNAL ;
    PORT
      LAYER M3 ;
        RECT  2.484 0 2.502 0.144 ;
    END
  END o[4]
  PIN o[50]
    DIRECTION OUTPUT ;
    USE SIGNAL ;
    PORT
      LAYER M3 ;
        RECT  6.084 0 6.102 0.144 ;
    END
  END o[50]
  PIN o[51]
    DIRECTION OUTPUT ;
    USE SIGNAL ;
    PORT
      LAYER M5 ;
        RECT  6.144 0 6.168 0.192 ;
    END
  END o[51]
  PIN o[52]
    DIRECTION OUTPUT ;
    USE SIGNAL ;
    PORT
      LAYER M3 ;
        RECT  6.228 0 6.246 0.144 ;
    END
  END o[52]
  PIN o[53]
    DIRECTION OUTPUT ;
    USE SIGNAL ;
    PORT
      LAYER M5 ;
        RECT  6.336 0 6.36 0.192 ;
    END
  END o[53]
  PIN o[54]
    DIRECTION OUTPUT ;
    USE SIGNAL ;
    PORT
      LAYER M3 ;
        RECT  6.408 0 6.426 0.144 ;
    END
  END o[54]
  PIN o[55]
    DIRECTION OUTPUT ;
    USE SIGNAL ;
    PORT
      LAYER M5 ;
        RECT  6.48 0 6.504 0.192 ;
    END
  END o[55]
  PIN o[56]
    DIRECTION OUTPUT ;
    USE SIGNAL ;
    PORT
      LAYER M3 ;
        RECT  6.552 0 6.57 0.144 ;
    END
  END o[56]
  PIN o[57]
    DIRECTION OUTPUT ;
    USE SIGNAL ;
    PORT
      LAYER M5 ;
        RECT  6.624 0 6.648 0.192 ;
    END
  END o[57]
  PIN o[58]
    DIRECTION OUTPUT ;
    USE SIGNAL ;
    PORT
      LAYER M3 ;
        RECT  6.696 0 6.714 0.144 ;
    END
  END o[58]
  PIN o[59]
    DIRECTION OUTPUT ;
    USE SIGNAL ;
    PORT
      LAYER M5 ;
        RECT  6.768 0 6.792 0.192 ;
    END
  END o[59]
  PIN o[5]
    DIRECTION OUTPUT ;
    USE SIGNAL ;
    PORT
      LAYER M5 ;
        RECT  2.592 0 2.616 0.192 ;
    END
  END o[5]
  PIN o[60]
    DIRECTION OUTPUT ;
    USE SIGNAL ;
    PORT
      LAYER M3 ;
        RECT  6.876 0 6.894 0.144 ;
    END
  END o[60]
  PIN o[61]
    DIRECTION OUTPUT ;
    USE SIGNAL ;
    PORT
      LAYER M5 ;
        RECT  6.96 0 6.984 0.192 ;
    END
  END o[61]
  PIN o[62]
    DIRECTION OUTPUT ;
    USE SIGNAL ;
    PORT
      LAYER M3 ;
        RECT  7.02 0 7.038 0.144 ;
    END
  END o[62]
  PIN o[63]
    DIRECTION OUTPUT ;
    USE SIGNAL ;
    PORT
      LAYER M5 ;
        RECT  7.104 0 7.128 0.192 ;
    END
  END o[63]
  PIN o[64]
    DIRECTION OUTPUT ;
    USE SIGNAL ;
    PORT
      LAYER M3 ;
        RECT  7.164 0 7.182 0.144 ;
    END
  END o[64]
  PIN o[65]
    DIRECTION OUTPUT ;
    USE SIGNAL ;
    PORT
      LAYER M5 ;
        RECT  7.248 0 7.272 0.192 ;
    END
  END o[65]
  PIN o[66]
    DIRECTION OUTPUT ;
    USE SIGNAL ;
    PORT
      LAYER M3 ;
        RECT  7.344 0 7.362 0.144 ;
    END
  END o[66]
  PIN o[67]
    DIRECTION OUTPUT ;
    USE SIGNAL ;
    PORT
      LAYER M5 ;
        RECT  7.392 0 7.416 0.192 ;
    END
  END o[67]
  PIN o[68]
    DIRECTION OUTPUT ;
    USE SIGNAL ;
    PORT
      LAYER M3 ;
        RECT  7.488 0 7.506 0.144 ;
    END
  END o[68]
  PIN o[69]
    DIRECTION OUTPUT ;
    USE SIGNAL ;
    PORT
      LAYER M5 ;
        RECT  7.584 0 7.608 0.192 ;
    END
  END o[69]
  PIN o[6]
    DIRECTION OUTPUT ;
    USE SIGNAL ;
    PORT
      LAYER M3 ;
        RECT  2.664 0 2.682 0.144 ;
    END
  END o[6]
  PIN o[70]
    DIRECTION OUTPUT ;
    USE SIGNAL ;
    PORT
      LAYER M3 ;
        RECT  7.632 0 7.65 0.144 ;
    END
  END o[70]
  PIN o[71]
    DIRECTION OUTPUT ;
    USE SIGNAL ;
    PORT
      LAYER M5 ;
        RECT  7.728 0 7.752 0.192 ;
    END
  END o[71]
  PIN o[72]
    DIRECTION OUTPUT ;
    USE SIGNAL ;
    PORT
      LAYER M3 ;
        RECT  7.812 0 7.83 0.144 ;
    END
  END o[72]
  PIN o[73]
    DIRECTION OUTPUT ;
    USE SIGNAL ;
    PORT
      LAYER M5 ;
        RECT  7.872 0 7.896 0.192 ;
    END
  END o[73]
  PIN o[74]
    DIRECTION OUTPUT ;
    USE SIGNAL ;
    PORT
      LAYER M3 ;
        RECT  7.956 0 7.974 0.144 ;
    END
  END o[74]
  PIN o[75]
    DIRECTION OUTPUT ;
    USE SIGNAL ;
    PORT
      LAYER M5 ;
        RECT  8.016 0 8.04 0.192 ;
    END
  END o[75]
  PIN o[76]
    DIRECTION OUTPUT ;
    USE SIGNAL ;
    PORT
      LAYER M3 ;
        RECT  8.1 0 8.118 0.144 ;
    END
  END o[76]
  PIN o[77]
    DIRECTION OUTPUT ;
    USE SIGNAL ;
    PORT
      LAYER M5 ;
        RECT  8.208 0 8.232 0.192 ;
    END
  END o[77]
  PIN o[78]
    DIRECTION OUTPUT ;
    USE SIGNAL ;
    PORT
      LAYER M3 ;
        RECT  8.28 0 8.298 0.144 ;
    END
  END o[78]
  PIN o[79]
    DIRECTION OUTPUT ;
    USE SIGNAL ;
    PORT
      LAYER M5 ;
        RECT  8.352 0 8.376 0.192 ;
    END
  END o[79]
  PIN o[7]
    DIRECTION OUTPUT ;
    USE SIGNAL ;
    PORT
      LAYER M5 ;
        RECT  2.736 0 2.76 0.192 ;
    END
  END o[7]
  PIN o[80]
    DIRECTION OUTPUT ;
    USE SIGNAL ;
    PORT
      LAYER M3 ;
        RECT  8.424 0 8.442 0.144 ;
    END
  END o[80]
  PIN o[81]
    DIRECTION OUTPUT ;
    USE SIGNAL ;
    PORT
      LAYER M5 ;
        RECT  8.496 0 8.52 0.192 ;
    END
  END o[81]
  PIN o[82]
    DIRECTION OUTPUT ;
    USE SIGNAL ;
    PORT
      LAYER M3 ;
        RECT  8.568 0 8.586 0.144 ;
    END
  END o[82]
  PIN o[83]
    DIRECTION OUTPUT ;
    USE SIGNAL ;
    PORT
      LAYER M5 ;
        RECT  8.64 0 8.664 0.192 ;
    END
  END o[83]
  PIN o[84]
    DIRECTION OUTPUT ;
    USE SIGNAL ;
    PORT
      LAYER M3 ;
        RECT  8.748 0 8.766 0.144 ;
    END
  END o[84]
  PIN o[85]
    DIRECTION OUTPUT ;
    USE SIGNAL ;
    PORT
      LAYER M5 ;
        RECT  8.832 0 8.856 0.192 ;
    END
  END o[85]
  PIN o[86]
    DIRECTION OUTPUT ;
    USE SIGNAL ;
    PORT
      LAYER M3 ;
        RECT  8.892 0 8.91 0.144 ;
    END
  END o[86]
  PIN o[87]
    DIRECTION OUTPUT ;
    USE SIGNAL ;
    PORT
      LAYER M5 ;
        RECT  8.976 0 9 0.192 ;
    END
  END o[87]
  PIN o[88]
    DIRECTION OUTPUT ;
    USE SIGNAL ;
    PORT
      LAYER M3 ;
        RECT  9.036 0 9.054 0.144 ;
    END
  END o[88]
  PIN o[89]
    DIRECTION OUTPUT ;
    USE SIGNAL ;
    PORT
      LAYER M5 ;
        RECT  9.12 0 9.144 0.192 ;
    END
  END o[89]
  PIN o[8]
    DIRECTION OUTPUT ;
    USE SIGNAL ;
    PORT
      LAYER M3 ;
        RECT  2.808 0 2.826 0.144 ;
    END
  END o[8]
  PIN o[90]
    DIRECTION OUTPUT ;
    USE SIGNAL ;
    PORT
      LAYER M3 ;
        RECT  9.216 0 9.234 0.144 ;
    END
  END o[90]
  PIN o[91]
    DIRECTION OUTPUT ;
    USE SIGNAL ;
    PORT
      LAYER M5 ;
        RECT  9.264 0 9.288 0.192 ;
    END
  END o[91]
  PIN o[92]
    DIRECTION OUTPUT ;
    USE SIGNAL ;
    PORT
      LAYER M3 ;
        RECT  9.36 0 9.378 0.144 ;
    END
  END o[92]
  PIN o[93]
    DIRECTION OUTPUT ;
    USE SIGNAL ;
    PORT
      LAYER M5 ;
        RECT  9.456 0 9.48 0.192 ;
    END
  END o[93]
  PIN o[94]
    DIRECTION OUTPUT ;
    USE SIGNAL ;
    PORT
      LAYER M3 ;
        RECT  9.504 0 9.522 0.144 ;
    END
  END o[94]
  PIN o[95]
    DIRECTION OUTPUT ;
    USE SIGNAL ;
    PORT
      LAYER M5 ;
        RECT  9.6 0 9.624 0.192 ;
    END
  END o[95]
  PIN o[96]
    DIRECTION OUTPUT ;
    USE SIGNAL ;
    PORT
      LAYER M3 ;
        RECT  9.684 0 9.702 0.144 ;
    END
  END o[96]
  PIN o[97]
    DIRECTION OUTPUT ;
    USE SIGNAL ;
    PORT
      LAYER M5 ;
        RECT  9.744 0 9.768 0.192 ;
    END
  END o[97]
  PIN o[98]
    DIRECTION OUTPUT ;
    USE SIGNAL ;
    PORT
      LAYER M3 ;
        RECT  9.828 0 9.846 0.144 ;
    END
  END o[98]
  PIN o[99]
    DIRECTION OUTPUT ;
    USE SIGNAL ;
    PORT
      LAYER M5 ;
        RECT  9.888 0 9.912 0.192 ;
    END
  END o[99]
  PIN o[9]
    DIRECTION OUTPUT ;
    USE SIGNAL ;
    PORT
      LAYER M5 ;
        RECT  2.88 0 2.904 0.192 ;
    END
  END o[9]
  PIN rs
    DIRECTION INPUT ;
    USE SIGNAL ;
    PORT
      LAYER M4 ;
        RECT  25.728 11.904 25.92 11.928 ;
    END
    PORT
      LAYER M4 ;
        RECT  25.657 11.424 25.74 11.928 ;
    END
  END rs
  PIN VDD
    DIRECTION INOUT ;
    USE POWER ;
    PORT
      LAYER M5 ;
        RECT  21.492 2.151 21.612 15.129 ;
        RECT  18.792 2.151 18.912 15.129 ;
        RECT  16.092 2.151 16.212 15.129 ;
        RECT  13.392 2.151 13.512 15.129 ;
        RECT  10.692 2.151 10.812 15.129 ;
        RECT  7.992 2.151 8.112 15.129 ;
        RECT  5.292 2.151 5.412 15.129 ;
        RECT  2.592 2.151 2.712 15.129 ;
    END
  END VDD
  PIN VSS
    DIRECTION INOUT ;
    USE GROUND ;
    PORT
      LAYER M5 ;
        RECT  21.3 2.137 21.42 15.143 ;
        RECT  18.6 2.137 18.72 15.143 ;
        RECT  15.9 2.137 16.02 15.143 ;
        RECT  13.2 2.137 13.32 15.143 ;
        RECT  10.5 2.137 10.62 15.143 ;
        RECT  7.8 2.137 7.92 15.143 ;
        RECT  5.1 2.137 5.22 15.143 ;
        RECT  2.4 2.137 2.52 15.143 ;
    END
  END VSS
  # OT_OBS_CLOSED layer=M5 d_um=1.536 added=16
  OBS
    LAYER RVTN ;
     RECT  2.16 2.16 23.76 2.295 ;
     RECT  2.16 2.565 23.76 2.835 ;
     RECT  2.16 3.105 23.76 3.375 ;
     RECT  2.16 3.645 23.76 3.915 ;
     RECT  2.16 4.185 23.76 4.455 ;
     RECT  2.16 4.725 23.76 4.995 ;
     RECT  2.16 5.265 23.76 5.535 ;
     RECT  2.16 5.805 23.76 6.075 ;
     RECT  2.16 6.345 23.76 6.615 ;
     RECT  2.16 6.885 23.76 7.155 ;
     RECT  2.16 7.425 23.76 7.695 ;
     RECT  2.16 7.965 23.76 8.235 ;
     RECT  2.16 8.505 23.76 8.775 ;
     RECT  2.16 9.045 23.76 9.315 ;
     RECT  2.16 9.585 23.76 9.855 ;
     RECT  2.16 10.125 23.76 10.395 ;
     RECT  2.16 10.665 23.76 10.935 ;
     RECT  2.16 11.205 23.76 11.475 ;
     RECT  2.16 11.745 23.76 12.015 ;
     RECT  2.16 12.285 23.76 12.555 ;
     RECT  2.16 12.825 23.76 13.095 ;
     RECT  2.16 13.365 23.76 13.635 ;
     RECT  2.16 13.905 23.76 14.175 ;
     RECT  2.16 14.445 23.76 14.715 ;
     RECT  2.16 14.985 23.76 15.12 ;
    LAYER RVTP ;
     RECT  2.16 2.295 23.76 2.565 ;
     RECT  2.16 2.835 23.76 3.105 ;
     RECT  2.16 3.375 23.76 3.645 ;
     RECT  2.16 3.915 23.76 4.185 ;
     RECT  2.16 4.455 23.76 4.725 ;
     RECT  2.16 4.995 23.76 5.265 ;
     RECT  2.16 5.535 23.76 5.805 ;
     RECT  2.16 6.075 23.76 6.345 ;
     RECT  2.16 6.615 23.76 6.885 ;
     RECT  2.16 7.155 23.76 7.425 ;
     RECT  2.16 7.695 23.76 7.965 ;
     RECT  2.16 8.235 23.76 8.505 ;
     RECT  2.16 8.775 23.76 9.045 ;
     RECT  2.16 9.315 23.76 9.585 ;
     RECT  2.16 9.855 23.76 10.125 ;
     RECT  2.16 10.395 23.76 10.665 ;
     RECT  2.16 10.935 23.76 11.205 ;
     RECT  2.16 11.475 23.76 11.745 ;
     RECT  2.16 12.015 23.76 12.285 ;
     RECT  2.16 12.555 23.76 12.825 ;
     RECT  2.16 13.095 23.76 13.365 ;
     RECT  2.16 13.635 23.76 13.905 ;
     RECT  2.16 14.175 23.76 14.445 ;
     RECT  2.16 14.715 23.76 14.985 ;
    LAYER M1 ;
     RECT  2.16 2.151 23.76 15.129 ;
    LAYER M2 ;
     RECT  0.931 5.508 0.967 5.526 ;
     RECT  0.967 5.508 1.003 6.138 ;
     RECT  0.895 15.156 1.003 15.174 ;
     RECT  1.003 5.508 1.039 6.264 ;
     RECT  0.967 13.68 1.039 13.698 ;
     RECT  1.003 14.796 1.039 15.174 ;
     RECT  1.075 3.618 1.579 3.636 ;
     RECT  1.111 8.244 1.615 8.262 ;
     RECT  0.895 4.428 1.651 4.446 ;
     RECT  1.039 5.31 1.651 6.264 ;
     RECT  1.075 12.906 1.651 12.924 ;
     RECT  1.651 4.428 1.795 6.264 ;
     RECT  1.651 12.87 1.795 12.924 ;
     RECT  1.039 13.68 1.795 15.174 ;
     RECT  1.867 12.096 1.903 12.114 ;
     RECT  1.795 12.87 1.903 15.174 ;
     RECT  1.615 8.244 2.047 8.424 ;
     RECT  1.687 10.71 2.083 10.728 ;
     RECT  1.867 2.736 2.16 2.754 ;
     RECT  1.579 3.618 2.16 3.672 ;
     RECT  1.795 4.428 2.16 6.84 ;
     RECT  2.047 7.866 2.16 8.424 ;
     RECT  1.939 9.63 2.16 9.648 ;
     RECT  2.083 10.71 2.16 10.998 ;
     RECT  1.903 12.096 2.16 15.174 ;
     RECT  2.16 2.151 2.479 15.174 ;
     RECT  2.479 1.728 2.515 15.174 ;
     RECT  2.515 1.728 2.579 15.282 ;
     RECT  2.579 1.8 2.731 15.282 ;
     RECT  2.659 0.144 2.759 0.162 ;
     RECT  2.731 1.8 2.831 15.354 ;
     RECT  2.831 1.8 3.047 15.246 ;
     RECT  3.127 17.118 3.163 17.136 ;
     RECT  3.163 17.118 3.263 17.208 ;
     RECT  3.047 2.151 4.207 15.246 ;
     RECT  4.207 2.106 4.459 15.246 ;
     RECT  4.459 2.106 5.467 15.282 ;
     RECT  5.467 2.034 5.611 15.282 ;
     RECT  5.611 1.962 5.747 15.282 ;
     RECT  5.287 1.152 5.755 1.17 ;
     RECT  5.747 1.962 5.755 15.174 ;
     RECT  5.755 1.152 6.071 15.174 ;
     RECT  6.115 17.118 6.151 17.136 ;
     RECT  6.071 1.152 6.251 1.17 ;
     RECT  6.151 17.118 6.251 17.208 ;
     RECT  6.071 1.962 6.611 15.174 ;
     RECT  7.267 1.152 7.403 1.17 ;
     RECT  6.611 2.151 7.483 15.174 ;
     RECT  3.559 0.144 7.627 0.162 ;
     RECT  7.483 1.728 7.691 15.174 ;
     RECT  7.691 2.151 7.735 15.174 ;
     RECT  7.627 0.144 7.807 0.324 ;
     RECT  7.735 2.151 7.951 15.21 ;
     RECT  7.807 0.144 7.979 0.396 ;
     RECT  7.951 2.151 8.275 15.246 ;
     RECT  8.275 2.151 8.411 15.282 ;
     RECT  8.411 2.151 8.699 15.246 ;
     RECT  8.699 2.151 8.743 15.129 ;
     RECT  7.979 0.144 8.923 0.162 ;
     RECT  8.923 0.144 9.059 0.234 ;
     RECT  8.743 1.728 9.491 15.129 ;
     RECT  9.491 2.106 10.283 15.129 ;
     RECT  9.059 0.144 10.327 0.162 ;
     RECT  10.327 1.224 10.363 1.242 ;
     RECT  10.283 2.151 10.363 15.129 ;
     RECT  10.363 1.152 10.499 1.242 ;
     RECT  10.363 2.151 10.499 15.399 ;
     RECT  10.327 0.144 10.643 0.234 ;
     RECT  10.499 1.224 10.715 1.242 ;
     RECT  10.499 2.151 11.183 15.174 ;
     RECT  11.183 2.151 11.839 15.129 ;
     RECT  11.839 2.034 11.983 15.129 ;
     RECT  10.643 0.144 12.119 0.162 ;
     RECT  12.091 1.224 12.163 1.242 ;
     RECT  12.163 1.152 12.515 1.242 ;
     RECT  11.983 2.034 12.955 15.174 ;
     RECT  12.515 1.152 13.019 1.17 ;
     RECT  12.955 1.962 13.099 15.174 ;
     RECT  13.099 1.962 13.631 15.399 ;
     RECT  13.631 1.962 14.063 15.354 ;
     RECT  14.063 1.962 14.171 15.318 ;
     RECT  14.539 16.146 14.675 16.164 ;
     RECT  13.171 0.144 15.115 0.162 ;
     RECT  15.115 0.144 15.323 0.324 ;
     RECT  14.171 2.106 15.511 15.318 ;
     RECT  15.511 1.926 15.899 15.318 ;
     RECT  15.323 0.144 16.231 0.162 ;
     RECT  16.231 0.144 16.619 0.234 ;
     RECT  15.899 1.926 17.095 15.246 ;
     RECT  16.619 0.144 17.455 0.162 ;
     RECT  17.095 1.836 17.491 15.246 ;
     RECT  17.491 1.152 17.663 15.246 ;
     RECT  17.663 1.836 17.671 15.246 ;
     RECT  17.455 0.144 18.131 0.234 ;
     RECT  18.131 0.144 18.743 0.162 ;
     RECT  17.671 1.836 19.463 15.984 ;
     RECT  19.975 0.144 20.363 0.162 ;
     RECT  19.463 1.836 20.407 15.669 ;
     RECT  20.011 16.542 20.983 16.56 ;
     RECT  20.983 16.542 21.055 17.1 ;
     RECT  20.407 1.152 21.451 15.669 ;
     RECT  21.055 16.542 21.451 17.172 ;
     RECT  22.135 0.144 22.459 0.162 ;
     RECT  22.459 0.144 22.603 0.198 ;
     RECT  21.451 1.152 22.703 17.172 ;
     RECT  22.603 0.144 22.739 0.279 ;
     RECT  22.739 0.144 22.775 0.162 ;
     RECT  22.703 1.152 23.099 1.242 ;
     RECT  22.703 2.034 23.135 17.172 ;
     RECT  23.099 1.224 23.747 1.242 ;
     RECT  23.135 2.034 23.76 15.984 ;
     RECT  23.76 10.836 23.783 14.436 ;
     RECT  23.76 9.666 23.855 9.684 ;
     RECT  23.76 2.034 24.107 7.524 ;
     RECT  23.783 11.214 24.107 14.436 ;
     RECT  24.107 11.214 24.215 12.816 ;
     RECT  24.107 2.034 24.287 4.212 ;
     RECT  23.135 17.154 24.359 17.172 ;
     RECT  24.215 11.214 24.539 12.474 ;
     RECT  24.107 13.644 24.575 14.436 ;
     RECT  24.107 5.238 24.611 7.524 ;
     RECT  24.539 11.52 24.611 12.474 ;
     RECT  24.611 5.238 24.647 7.218 ;
     RECT  24.575 13.95 24.647 14.436 ;
     RECT  24.647 5.31 24.683 7.218 ;
     RECT  23.76 15.651 24.683 15.984 ;
     RECT  24.683 5.31 24.719 6.444 ;
     RECT  24.647 13.95 24.719 14.004 ;
     RECT  24.683 7.2 24.755 7.218 ;
     RECT  24.719 5.886 24.791 6.444 ;
     RECT  24.791 6.426 24.827 6.444 ;
     RECT  24.683 15.966 24.827 15.984 ;
     RECT  24.611 11.52 25.079 12.159 ;
     RECT  25.079 11.52 25.115 12.114 ;
     RECT  24.287 2.034 25.187 3.708 ;
     RECT  25.187 3.348 25.223 3.708 ;
     RECT  25.187 2.034 25.295 2.592 ;
     RECT  25.115 11.52 25.295 12.042 ;
     RECT  25.223 3.69 25.331 3.708 ;
     RECT  25.295 12.024 25.331 12.042 ;
     RECT  25.295 2.034 25.367 2.052 ;
     RECT  24.719 13.95 25.367 13.968 ;
    LAYER M3 ;
     RECT  2.214 0.108 2.34 0.144 ;
     RECT  2.358 0.108 2.484 0.144 ;
     RECT  2.502 0.108 2.664 0.144 ;
     RECT  2.682 0.108 2.808 0.144 ;
     RECT  2.826 0.108 2.952 0.144 ;
     RECT  2.97 0.108 3.132 0.144 ;
     RECT  3.15 0.108 3.276 0.144 ;
     RECT  3.294 0.108 3.42 0.144 ;
     RECT  3.438 0.108 3.6 0.144 ;
     RECT  3.618 0.108 3.744 0.144 ;
     RECT  3.762 0.108 3.888 0.144 ;
     RECT  3.906 0.108 4.068 0.144 ;
     RECT  4.086 0.108 4.212 0.144 ;
     RECT  4.23 0.108 4.356 0.144 ;
     RECT  4.374 0.108 4.536 0.144 ;
     RECT  4.554 0.108 4.68 0.144 ;
     RECT  4.698 0.108 4.824 0.144 ;
     RECT  4.842 0.108 5.004 0.144 ;
     RECT  5.022 0.108 5.148 0.144 ;
     RECT  5.166 0.108 5.292 0.144 ;
     RECT  5.31 0.108 5.472 0.144 ;
     RECT  5.49 0.108 5.616 0.144 ;
     RECT  5.634 0.108 5.76 0.144 ;
     RECT  5.778 0.108 5.94 0.144 ;
     RECT  5.958 0.108 6.084 0.144 ;
     RECT  6.102 0.108 6.228 0.144 ;
     RECT  6.246 0.108 6.408 0.144 ;
     RECT  6.426 0.108 6.552 0.144 ;
     RECT  6.57 0.108 6.696 0.144 ;
     RECT  6.714 0.108 6.876 0.144 ;
     RECT  6.894 0.108 7.02 0.144 ;
     RECT  7.038 0.108 7.164 0.144 ;
     RECT  7.182 0.108 7.344 0.144 ;
     RECT  7.362 0.108 7.488 0.144 ;
     RECT  7.506 0.108 7.632 0.144 ;
     RECT  7.65 0.108 7.812 0.144 ;
     RECT  7.83 0.108 7.956 0.144 ;
     RECT  7.974 0.108 8.1 0.144 ;
     RECT  8.118 0.108 8.28 0.144 ;
     RECT  8.298 0.108 8.424 0.144 ;
     RECT  8.442 0.108 8.568 0.144 ;
     RECT  8.586 0.108 8.748 0.144 ;
     RECT  8.766 0.108 8.892 0.144 ;
     RECT  8.91 0.108 9.036 0.144 ;
     RECT  9.054 0.108 9.216 0.144 ;
     RECT  9.234 0.108 9.36 0.144 ;
     RECT  9.378 0.108 9.504 0.144 ;
     RECT  9.522 0.108 9.684 0.144 ;
     RECT  9.702 0.108 9.828 0.144 ;
     RECT  9.846 0.108 9.972 0.144 ;
     RECT  9.99 0.108 10.152 0.144 ;
     RECT  10.17 0.108 10.296 0.144 ;
     RECT  10.314 0.108 10.44 0.144 ;
     RECT  10.458 0.108 10.62 0.144 ;
     RECT  10.638 0.108 10.764 0.144 ;
     RECT  10.782 0.108 10.908 0.144 ;
     RECT  10.926 0.108 11.088 0.144 ;
     RECT  11.106 0.108 11.232 0.144 ;
     RECT  11.25 0.108 11.376 0.144 ;
     RECT  11.394 0.108 11.556 0.144 ;
     RECT  11.574 0.108 11.7 0.144 ;
     RECT  11.718 0.108 11.844 0.144 ;
     RECT  11.862 0.108 12.024 0.144 ;
     RECT  12.042 0.108 12.168 0.144 ;
     RECT  12.186 0.108 12.312 0.144 ;
     RECT  12.33 0.108 12.492 0.144 ;
     RECT  12.51 0.108 12.636 0.144 ;
     RECT  12.654 0.108 12.78 0.144 ;
     RECT  12.798 0.108 12.96 0.144 ;
     RECT  12.978 0.108 13.104 0.144 ;
     RECT  13.122 0.108 13.248 0.144 ;
     RECT  13.266 0.108 13.428 0.144 ;
     RECT  13.446 0.108 13.572 0.144 ;
     RECT  13.59 0.108 13.716 0.144 ;
     RECT  13.734 0.108 13.896 0.144 ;
     RECT  13.914 0.108 14.04 0.144 ;
     RECT  14.058 0.108 14.184 0.144 ;
     RECT  14.202 0.108 14.364 0.144 ;
     RECT  14.382 0.108 14.508 0.144 ;
     RECT  14.526 0.108 14.652 0.144 ;
     RECT  14.67 0.108 14.832 0.144 ;
     RECT  14.85 0.108 14.976 0.144 ;
     RECT  14.994 0.108 15.12 0.144 ;
     RECT  15.138 0.108 15.3 0.144 ;
     RECT  15.318 0.108 15.444 0.144 ;
     RECT  15.462 0.108 15.588 0.144 ;
     RECT  15.606 0.108 15.768 0.144 ;
     RECT  15.786 0.108 15.912 0.144 ;
     RECT  15.93 0.108 16.056 0.144 ;
     RECT  16.074 0.108 16.236 0.144 ;
     RECT  16.254 0.108 16.38 0.144 ;
     RECT  16.398 0.108 16.524 0.144 ;
     RECT  16.542 0.108 16.704 0.144 ;
     RECT  16.722 0.108 16.848 0.144 ;
     RECT  16.866 0.108 16.992 0.144 ;
     RECT  17.01 0.108 17.172 0.144 ;
     RECT  17.19 0.108 17.316 0.144 ;
     RECT  17.334 0.108 17.46 0.144 ;
     RECT  17.478 0.108 17.64 0.144 ;
     RECT  17.658 0.108 17.784 0.144 ;
     RECT  17.802 0.108 17.928 0.144 ;
     RECT  17.946 0.108 18.108 0.144 ;
     RECT  18.126 0.108 18.252 0.144 ;
     RECT  18.27 0.108 18.396 0.144 ;
     RECT  18.414 0.108 18.576 0.144 ;
     RECT  18.594 0.108 18.72 0.144 ;
     RECT  18.738 0.108 18.864 0.144 ;
     RECT  18.882 0.108 19.044 0.144 ;
     RECT  19.062 0.108 19.188 0.144 ;
     RECT  19.206 0.108 19.332 0.144 ;
     RECT  19.35 0.108 19.512 0.144 ;
     RECT  19.53 0.108 19.656 0.144 ;
     RECT  19.674 0.108 19.8 0.144 ;
     RECT  19.818 0.108 19.98 0.144 ;
     RECT  19.998 0.108 20.124 0.144 ;
     RECT  20.142 0.108 20.268 0.144 ;
     RECT  20.286 0.108 20.448 0.144 ;
     RECT  20.466 0.108 20.592 0.144 ;
     RECT  20.61 0.108 20.736 0.144 ;
     RECT  20.754 0.108 20.916 0.144 ;
     RECT  20.934 0.108 21.06 0.144 ;
     RECT  21.078 0.108 21.204 0.144 ;
     RECT  21.222 0.108 21.384 0.144 ;
     RECT  21.402 0.108 21.528 0.144 ;
     RECT  21.546 0.108 21.672 0.144 ;
     RECT  21.69 0.108 21.852 0.144 ;
     RECT  21.87 0.108 21.996 0.144 ;
     RECT  22.014 0.108 22.14 0.144 ;
     RECT  22.158 0.108 22.32 0.144 ;
     RECT  22.338 0.108 22.464 0.144 ;
     RECT  22.482 0.108 22.608 0.144 ;
     RECT  22.626 0.108 22.788 0.144 ;
     RECT  22.806 0.108 22.932 0.144 ;
     RECT  22.95 0.108 23.076 0.144 ;
     RECT  23.094 0.108 23.256 0.144 ;
     RECT  23.274 0.108 23.4 0.144 ;
     RECT  23.418 0.108 23.544 0.144 ;
     RECT  23.562 0.108 23.724 0.144 ;
     RECT  2.196 0.144 23.742 1.247 ;
     RECT  2.196 1.247 23.562 2.101 ;
     RECT  2.196 2.101 23.778 2.371 ;
     RECT  25.344 2.029 25.362 2.533 ;
     RECT  2.196 2.371 24.246 2.731 ;
     RECT  1.872 2.731 24.246 2.803 ;
     RECT  25.236 2.533 25.362 3.181 ;
     RECT  1.872 2.803 24.318 3.415 ;
     RECT  25.128 3.181 25.362 3.415 ;
     RECT  1.08 3.613 1.098 3.649 ;
     RECT  1.872 3.415 25.362 3.649 ;
     RECT  1.08 3.649 25.362 4.423 ;
     RECT  0.9 4.423 25.362 7.435 ;
     RECT  0.9 7.435 25.758 11.453 ;
     RECT  0.9 11.453 25.686 11.933 ;
     RECT  0.9 11.933 25.362 13.973 ;
     RECT  0.9 13.973 24.858 15.179 ;
     RECT  1.62 15.179 24.858 15.677 ;
     RECT  2.196 15.677 24.858 16.589 ;
     RECT  2.196 16.589 24.354 17.136 ;
     RECT  2.214 17.136 2.34 17.148 ;
     RECT  2.358 17.136 2.52 17.148 ;
     RECT  2.538 17.136 2.664 17.148 ;
     RECT  2.682 17.136 2.808 17.148 ;
     RECT  2.826 17.136 2.988 17.148 ;
     RECT  3.006 17.136 3.132 17.148 ;
     RECT  3.15 17.136 3.276 17.148 ;
     RECT  3.294 17.136 3.456 17.148 ;
     RECT  3.474 17.136 3.6 17.148 ;
     RECT  3.618 17.136 3.744 17.148 ;
     RECT  3.762 17.136 3.924 17.148 ;
     RECT  3.942 17.136 4.068 17.148 ;
     RECT  4.086 17.136 4.212 17.148 ;
     RECT  4.23 17.136 4.392 17.148 ;
     RECT  4.41 17.136 4.536 17.148 ;
     RECT  4.554 17.136 4.68 17.148 ;
     RECT  4.698 17.136 4.86 17.148 ;
     RECT  4.878 17.136 5.004 17.148 ;
     RECT  5.022 17.136 5.148 17.148 ;
     RECT  5.166 17.136 5.328 17.148 ;
     RECT  5.346 17.136 5.472 17.148 ;
     RECT  5.49 17.136 5.616 17.148 ;
     RECT  5.634 17.136 5.796 17.148 ;
     RECT  5.814 17.136 5.94 17.148 ;
     RECT  5.958 17.136 6.12 17.148 ;
     RECT  6.138 17.136 6.264 17.148 ;
     RECT  6.282 17.136 6.408 17.148 ;
     RECT  6.426 17.136 6.588 17.148 ;
     RECT  6.606 17.136 6.732 17.148 ;
     RECT  6.75 17.136 6.876 17.148 ;
     RECT  6.894 17.136 7.056 17.148 ;
     RECT  7.074 17.136 7.2 17.148 ;
     RECT  7.218 17.136 7.344 17.148 ;
     RECT  7.362 17.136 7.524 17.148 ;
     RECT  7.542 17.136 7.668 17.148 ;
     RECT  7.686 17.136 7.812 17.148 ;
     RECT  7.83 17.136 7.992 17.148 ;
     RECT  8.01 17.136 8.136 17.148 ;
     RECT  8.154 17.136 8.28 17.148 ;
     RECT  8.298 17.136 8.46 17.148 ;
     RECT  8.478 17.136 8.604 17.148 ;
     RECT  8.622 17.136 8.748 17.148 ;
     RECT  8.766 17.136 8.928 17.148 ;
     RECT  8.946 17.136 9.072 17.148 ;
     RECT  9.09 17.136 9.216 17.148 ;
     RECT  9.234 17.136 9.396 17.148 ;
     RECT  9.414 17.136 9.54 17.148 ;
     RECT  9.558 17.136 9.72 17.148 ;
     RECT  9.738 17.136 9.864 17.148 ;
     RECT  9.882 17.136 10.008 17.148 ;
     RECT  10.026 17.136 10.188 17.148 ;
     RECT  10.206 17.136 10.332 17.148 ;
     RECT  10.35 17.136 10.476 17.148 ;
     RECT  10.494 17.136 10.656 17.148 ;
     RECT  10.674 17.136 10.8 17.148 ;
     RECT  10.818 17.136 10.944 17.148 ;
     RECT  10.962 17.136 11.124 17.148 ;
     RECT  11.142 17.136 11.268 17.148 ;
     RECT  11.286 17.136 11.412 17.148 ;
     RECT  11.43 17.136 11.592 17.148 ;
     RECT  11.61 17.136 11.736 17.148 ;
     RECT  11.754 17.136 11.88 17.148 ;
     RECT  11.898 17.136 12.06 17.148 ;
     RECT  12.078 17.136 12.204 17.148 ;
     RECT  12.222 17.136 12.348 17.148 ;
     RECT  12.366 17.136 12.528 17.148 ;
     RECT  12.546 17.136 12.672 17.148 ;
     RECT  12.69 17.136 12.816 17.148 ;
     RECT  12.834 17.136 12.996 17.148 ;
     RECT  13.014 17.136 13.14 17.148 ;
     RECT  13.158 17.136 13.32 17.148 ;
     RECT  13.338 17.136 13.464 17.148 ;
     RECT  13.482 17.136 13.608 17.148 ;
     RECT  13.626 17.136 13.788 17.148 ;
     RECT  13.806 17.136 13.932 17.148 ;
     RECT  13.95 17.136 14.076 17.148 ;
     RECT  14.094 17.136 14.256 17.148 ;
     RECT  14.274 17.136 14.4 17.148 ;
     RECT  14.418 17.136 14.544 17.148 ;
     RECT  14.562 17.136 14.724 17.148 ;
     RECT  14.742 17.136 14.868 17.148 ;
     RECT  14.886 17.136 15.012 17.148 ;
     RECT  15.03 17.136 15.192 17.148 ;
     RECT  15.21 17.136 15.336 17.148 ;
     RECT  15.354 17.136 15.48 17.148 ;
     RECT  15.498 17.136 15.66 17.148 ;
     RECT  15.678 17.136 15.804 17.148 ;
     RECT  15.822 17.136 15.948 17.148 ;
     RECT  15.966 17.136 16.128 17.148 ;
     RECT  16.146 17.136 16.272 17.148 ;
     RECT  16.29 17.136 16.416 17.148 ;
     RECT  16.434 17.136 16.596 17.148 ;
     RECT  16.614 17.136 16.74 17.148 ;
     RECT  16.758 17.136 16.92 17.148 ;
     RECT  16.938 17.136 17.064 17.148 ;
     RECT  17.082 17.136 17.208 17.148 ;
     RECT  17.226 17.136 17.388 17.148 ;
     RECT  17.406 17.136 17.532 17.148 ;
     RECT  17.55 17.136 17.676 17.148 ;
     RECT  17.694 17.136 17.856 17.148 ;
     RECT  17.874 17.136 18 17.148 ;
     RECT  18.018 17.136 18.144 17.148 ;
     RECT  18.162 17.136 18.324 17.148 ;
     RECT  18.342 17.136 18.468 17.148 ;
     RECT  18.486 17.136 18.612 17.148 ;
     RECT  18.63 17.136 18.792 17.148 ;
     RECT  18.81 17.136 18.936 17.148 ;
     RECT  18.954 17.136 19.08 17.148 ;
     RECT  19.098 17.136 19.26 17.148 ;
     RECT  19.278 17.136 19.404 17.148 ;
     RECT  19.422 17.136 19.548 17.148 ;
     RECT  19.566 17.136 19.728 17.148 ;
     RECT  19.746 17.136 19.872 17.148 ;
     RECT  19.89 17.136 20.016 17.148 ;
     RECT  20.034 17.136 20.196 17.148 ;
     RECT  20.214 17.136 20.34 17.148 ;
     RECT  20.358 17.136 20.52 17.148 ;
     RECT  20.538 17.136 20.664 17.148 ;
     RECT  20.682 17.136 20.808 17.148 ;
     RECT  20.826 17.136 20.988 17.148 ;
     RECT  21.006 17.136 21.132 17.148 ;
     RECT  21.15 17.136 21.276 17.148 ;
     RECT  21.294 17.136 21.456 17.148 ;
     RECT  21.474 17.136 21.6 17.148 ;
     RECT  21.618 17.136 21.744 17.148 ;
     RECT  21.762 17.136 21.924 17.148 ;
     RECT  21.942 17.136 22.068 17.148 ;
     RECT  22.086 17.136 22.212 17.148 ;
     RECT  22.23 17.136 22.392 17.148 ;
     RECT  22.41 17.136 22.536 17.148 ;
     RECT  22.554 17.136 22.68 17.148 ;
     RECT  22.698 17.136 22.86 17.148 ;
     RECT  22.878 17.136 23.004 17.148 ;
     RECT  23.022 17.136 23.148 17.148 ;
     RECT  23.166 17.136 23.328 17.148 ;
     RECT  23.346 17.136 23.472 17.148 ;
     RECT  23.49 17.136 23.616 17.148 ;
     RECT  23.634 17.136 24.354 17.148 ;
     RECT  21.06 17.148 21.078 17.177 ;
     RECT  24.336 17.148 24.354 17.177 ;
     RECT  3.168 17.148 3.258 17.213 ;
     RECT  6.156 17.148 6.246 17.213 ;
    LAYER M4 ;
     RECT  0.469 14.16 0.517 14.184 ;
     RECT  0.517 13.344 0.757 14.184 ;
     RECT  0.757 12.432 0.805 15.048 ;
     RECT  0.517 2.256 0.853 2.28 ;
     RECT  0.805 12.432 0.853 15.24 ;
     RECT  0.805 4.128 0.901 4.152 ;
     RECT  0.853 2.256 0.949 3.048 ;
     RECT  0.901 4.128 0.949 4.968 ;
     RECT  0.949 2.256 0.997 4.968 ;
     RECT  0.469 8.832 1.045 8.856 ;
     RECT  1.045 8.208 1.093 8.856 ;
     RECT  1.1 11.424 1.189 11.448 ;
     RECT  0.997 2.256 1.429 5.016 ;
     RECT  0.853 12.432 1.573 15.336 ;
     RECT  1.573 11.712 1.609 15.336 ;
     RECT  1.093 8.016 1.957 8.856 ;
     RECT  1.621 10.176 1.957 10.2 ;
     RECT  1.429 2.064 2.285 5.016 ;
     RECT  1.957 8.016 2.293 10.2 ;
     RECT  2.285 2.064 2.389 5.16 ;
     RECT  2.389 1.776 2.408 5.16 ;
     RECT  2.293 8.016 2.408 10.344 ;
     RECT  1.609 11.712 2.408 15.672 ;
     RECT  2.293 0.384 2.581 0.408 ;
     RECT  2.408 1.776 2.704 15.672 ;
     RECT  2.581 0.288 2.819 0.408 ;
     RECT  2.704 1.776 3.013 6.312 ;
     RECT  2.704 7.392 3.013 15.672 ;
     RECT  3.013 7.392 3.125 16.584 ;
     RECT  3.125 7.968 3.539 16.584 ;
     RECT  3.539 7.968 3.635 15.672 ;
     RECT  3.013 1.728 3.797 6.312 ;
     RECT  3.797 1.728 3.845 6.888 ;
     RECT  3.845 2.208 3.881 6.888 ;
     RECT  3.493 0.576 3.952 0.6 ;
     RECT  3.952 0.576 4.061 0.648 ;
     RECT  4.061 0.576 4.817 0.6 ;
     RECT  3.881 2.208 4.957 6.264 ;
     RECT  4.957 2.016 4.981 6.264 ;
     RECT  4.981 2.016 5.108 6.648 ;
     RECT  3.635 8.016 5.108 15.672 ;
     RECT  5.108 2.016 5.365 15.672 ;
     RECT  5.365 1.728 5.404 15.672 ;
     RECT  5.404 7.776 5.701 15.672 ;
     RECT  5.404 1.728 5.897 6.648 ;
     RECT  5.221 0.288 5.989 0.312 ;
     RECT  5.989 0.192 6.185 0.312 ;
     RECT  5.897 1.728 6.325 5.256 ;
     RECT  5.897 6.288 6.397 6.648 ;
     RECT  5.701 7.776 6.397 16.584 ;
     RECT  6.325 1.152 6.437 5.256 ;
     RECT  6.437 1.728 6.949 5.256 ;
     RECT  6.397 6.288 6.949 16.584 ;
     RECT  6.949 1.728 7.117 16.584 ;
     RECT  7.117 1.728 7.513 16.632 ;
     RECT  7.513 1.728 8.104 17.016 ;
     RECT  8.104 1.728 8.965 5.16 ;
     RECT  8.965 1.632 9.101 5.16 ;
     RECT  8.104 6.624 9.203 17.016 ;
     RECT  9.203 6.624 9.817 15.672 ;
     RECT  9.877 0.576 10.117 0.6 ;
     RECT  10.117 0.144 10.349 0.6 ;
     RECT  9.101 1.68 10.349 5.16 ;
     RECT  10.349 0.144 10.508 5.16 ;
     RECT  9.817 6.288 10.508 15.672 ;
     RECT  10.508 0.144 10.693 15.672 ;
     RECT  9.203 16.992 10.693 17.016 ;
     RECT  10.693 0.144 10.739 17.016 ;
     RECT  10.739 1.152 10.804 17.016 ;
     RECT  10.804 1.152 10.973 6.312 ;
     RECT  10.804 7.392 11.027 17.016 ;
     RECT  11.027 7.392 11.075 16.68 ;
     RECT  10.973 1.728 11.189 6.312 ;
     RECT  11.189 4.992 11.225 6.312 ;
     RECT  11.189 1.728 11.513 3.96 ;
     RECT  11.513 1.728 11.549 2.52 ;
     RECT  11.225 5.136 11.893 6.312 ;
     RECT  11.075 7.392 11.893 16.584 ;
     RECT  11.893 5.136 11.953 16.584 ;
     RECT  11.549 1.728 12.089 2.088 ;
     RECT  11.953 5.136 12.233 16.248 ;
     RECT  10.739 0.144 12.365 0.168 ;
     RECT  12.365 0.144 12.373 0.216 ;
     RECT  12.089 1.728 12.373 1.752 ;
     RECT  12.373 0.144 12.521 1.752 ;
     RECT  11.513 3.648 12.553 3.96 ;
     RECT  12.553 3.648 12.697 4.536 ;
     RECT  12.521 0.144 12.701 0.552 ;
     RECT  12.701 0.144 12.989 0.312 ;
     RECT  12.521 1.728 13.129 1.752 ;
     RECT  13.129 1.728 13.208 2.04 ;
     RECT  12.697 3.12 13.208 4.536 ;
     RECT  12.233 5.52 13.208 16.248 ;
     RECT  13.208 1.728 13.504 16.248 ;
     RECT  12.989 0.288 13.619 0.312 ;
     RECT  13.504 5.232 13.961 16.248 ;
     RECT  14.101 0.432 14.237 0.552 ;
     RECT  14.237 0.432 14.321 0.6 ;
     RECT  13.961 5.232 14.605 14.76 ;
     RECT  14.321 0.432 14.627 0.552 ;
     RECT  13.961 15.984 14.713 16.248 ;
     RECT  13.504 1.728 14.821 3.624 ;
     RECT  14.821 1.728 14.965 3.672 ;
     RECT  14.605 4.896 14.965 14.76 ;
     RECT  14.713 15.984 15.325 16.584 ;
     RECT  14.965 1.728 15.733 14.76 ;
     RECT  15.325 15.984 15.733 17.016 ;
     RECT  14.627 0.432 15.793 0.456 ;
     RECT  15.793 0.192 15.877 0.456 ;
     RECT  15.877 0.432 15.973 0.456 ;
     RECT  15.733 1.728 15.973 17.016 ;
     RECT  15.973 0.432 16.163 17.016 ;
     RECT  16.163 1.152 17.381 17.016 ;
     RECT  17.381 1.152 17.66 15.288 ;
     RECT  17.66 0.528 17.989 15.288 ;
     RECT  17.989 0.192 18.371 15.288 ;
     RECT  18.371 1.728 18.421 15.288 ;
     RECT  18.421 1.728 18.601 15.336 ;
     RECT  17.381 16.56 18.601 17.016 ;
     RECT  18.371 0.192 19.001 0.648 ;
     RECT  18.601 1.728 19.139 17.016 ;
     RECT  19.001 0.576 19.825 0.648 ;
     RECT  19.139 1.728 19.825 16.584 ;
     RECT  19.825 0.576 19.901 16.584 ;
     RECT  20.053 0.192 20.189 0.216 ;
     RECT  19.901 1.392 20.653 16.584 ;
     RECT  20.653 1.392 21.761 16.632 ;
     RECT  21.761 1.392 21.788 16.776 ;
     RECT  21.788 1.392 21.875 16.92 ;
     RECT  21.875 1.392 21.949 16.824 ;
     RECT  21.949 1.104 21.953 16.824 ;
     RECT  21.953 1.104 22.019 16.68 ;
     RECT  22.019 1.104 22.057 16.632 ;
     RECT  22.057 1.056 22.403 16.632 ;
     RECT  22.403 1.104 22.595 16.632 ;
     RECT  22.595 1.152 23.219 16.632 ;
     RECT  23.219 1.392 23.317 16.632 ;
     RECT  23.317 1.392 23.393 16.68 ;
     RECT  23.393 10.128 23.401 16.68 ;
     RECT  23.401 10.128 23.411 16.632 ;
     RECT  23.393 1.392 23.651 8.856 ;
     RECT  23.411 10.416 23.933 16.632 ;
     RECT  23.651 2.064 23.987 8.856 ;
     RECT  23.987 8.832 24.083 8.856 ;
     RECT  23.987 2.064 24.179 7.464 ;
     RECT  23.933 10.896 24.185 16.632 ;
     RECT  24.179 2.064 24.227 5.784 ;
     RECT  24.227 2.064 24.275 3.336 ;
     RECT  24.185 11.76 24.275 16.632 ;
     RECT  24.275 2.736 24.323 3.336 ;
     RECT  24.227 4.464 24.563 5.784 ;
     RECT  24.275 14.976 24.563 16.632 ;
     RECT  24.323 3.024 24.611 3.336 ;
     RECT  24.275 11.76 24.611 13.848 ;
     RECT  24.563 4.464 24.659 5.592 ;
     RECT  24.611 3.072 24.707 3.336 ;
     RECT  24.659 4.464 24.755 5.544 ;
     RECT  24.563 14.976 24.755 16.584 ;
     RECT  24.755 15.408 24.761 16.584 ;
     RECT  24.761 15.984 24.797 16.584 ;
     RECT  24.755 4.464 24.803 5.448 ;
     RECT  24.611 11.76 24.803 13.176 ;
     RECT  24.707 3.312 24.851 3.336 ;
     RECT  24.179 6.768 24.869 7.464 ;
     RECT  24.797 16.56 24.869 16.584 ;
     RECT  24.869 7.104 25.121 7.464 ;
     RECT  24.803 11.76 25.157 13.032 ;
     RECT  25.157 11.76 25.193 12.6 ;
     RECT  25.193 11.76 25.229 12.216 ;
     RECT  25.229 11.76 25.657 11.928 ;
     RECT  25.121 7.44 25.769 7.464 ;
     RECT  25.74 11.424 25.769 11.448 ;
    LAYER M5 ;
     RECT  10.128 0.133 10.152 0.144 ;
     RECT  2.28 0.144 2.4 0.192 ;
     RECT  2.424 0.144 2.592 0.192 ;
     RECT  2.616 0.144 2.736 0.192 ;
     RECT  2.76 0.144 2.88 0.192 ;
     RECT  2.904 0.144 3.024 0.192 ;
     RECT  3.048 0.144 3.216 0.192 ;
     RECT  3.24 0.144 3.36 0.192 ;
     RECT  3.384 0.144 3.504 0.192 ;
     RECT  3.528 0.144 3.648 0.192 ;
     RECT  3.672 0.144 3.84 0.192 ;
     RECT  3.864 0.144 3.984 0.192 ;
     RECT  4.008 0.144 4.128 0.192 ;
     RECT  4.152 0.144 4.272 0.192 ;
     RECT  4.296 0.144 4.464 0.192 ;
     RECT  4.488 0.144 4.608 0.192 ;
     RECT  4.632 0.144 4.752 0.192 ;
     RECT  4.776 0.144 4.896 0.192 ;
     RECT  4.92 0.144 5.088 0.192 ;
     RECT  5.112 0.144 5.232 0.192 ;
     RECT  5.256 0.144 5.376 0.192 ;
     RECT  5.4 0.144 5.52 0.192 ;
     RECT  5.544 0.144 5.712 0.192 ;
     RECT  5.736 0.144 5.856 0.192 ;
     RECT  5.88 0.144 6 0.192 ;
     RECT  6.024 0.144 6.144 0.192 ;
     RECT  6.168 0.144 6.336 0.192 ;
     RECT  6.36 0.144 6.48 0.192 ;
     RECT  6.504 0.144 6.624 0.192 ;
     RECT  6.648 0.144 6.768 0.192 ;
     RECT  6.792 0.144 6.96 0.192 ;
     RECT  6.984 0.144 7.104 0.192 ;
     RECT  7.128 0.144 7.248 0.192 ;
     RECT  7.272 0.144 7.392 0.192 ;
     RECT  7.416 0.144 7.584 0.192 ;
     RECT  7.608 0.144 7.728 0.192 ;
     RECT  7.752 0.144 7.872 0.192 ;
     RECT  7.896 0.144 8.016 0.192 ;
     RECT  8.04 0.144 8.208 0.192 ;
     RECT  8.232 0.144 8.352 0.192 ;
     RECT  8.376 0.144 8.496 0.192 ;
     RECT  8.52 0.144 8.64 0.192 ;
     RECT  8.664 0.144 8.832 0.192 ;
     RECT  8.856 0.144 8.976 0.192 ;
     RECT  9 0.144 9.12 0.192 ;
     RECT  9.144 0.144 9.264 0.192 ;
     RECT  9.288 0.144 9.456 0.192 ;
     RECT  9.48 0.144 9.6 0.192 ;
     RECT  9.624 0.144 9.744 0.192 ;
     RECT  9.768 0.144 9.888 0.192 ;
     RECT  9.912 0.144 10.08 0.192 ;
     RECT  10.104 0.144 10.224 0.192 ;
     RECT  10.248 0.144 10.368 0.192 ;
     RECT  10.392 0.144 10.512 0.192 ;
     RECT  10.536 0.144 10.704 0.192 ;
     RECT  10.728 0.144 10.848 0.192 ;
     RECT  10.872 0.144 10.992 0.192 ;
     RECT  11.016 0.144 11.136 0.192 ;
     RECT  11.16 0.144 11.328 0.192 ;
     RECT  11.352 0.144 11.472 0.192 ;
     RECT  11.496 0.144 11.616 0.192 ;
     RECT  11.64 0.144 11.76 0.192 ;
     RECT  11.784 0.144 11.952 0.192 ;
     RECT  11.976 0.144 12.096 0.192 ;
     RECT  12.12 0.144 12.24 0.192 ;
     RECT  12.264 0.144 12.384 0.192 ;
     RECT  12.408 0.144 12.576 0.192 ;
     RECT  12.6 0.144 12.72 0.192 ;
     RECT  12.744 0.144 12.864 0.192 ;
     RECT  12.888 0.144 13.008 0.192 ;
     RECT  13.032 0.144 13.2 0.192 ;
     RECT  13.224 0.144 13.344 0.192 ;
     RECT  13.368 0.144 13.488 0.192 ;
     RECT  13.512 0.144 13.632 0.192 ;
     RECT  13.656 0.144 13.824 0.192 ;
     RECT  13.848 0.144 13.968 0.192 ;
     RECT  13.992 0.144 14.112 0.192 ;
     RECT  14.136 0.144 14.256 0.192 ;
     RECT  14.28 0.144 14.448 0.192 ;
     RECT  14.472 0.144 14.592 0.192 ;
     RECT  14.616 0.144 14.736 0.192 ;
     RECT  14.76 0.144 14.88 0.192 ;
     RECT  14.904 0.144 15.072 0.192 ;
     RECT  15.096 0.144 15.216 0.192 ;
     RECT  15.24 0.144 15.36 0.192 ;
     RECT  15.384 0.144 15.504 0.192 ;
     RECT  15.528 0.144 15.696 0.192 ;
     RECT  15.72 0.144 15.84 0.192 ;
     RECT  15.864 0.144 15.984 0.192 ;
     RECT  16.008 0.144 16.128 0.192 ;
     RECT  16.152 0.144 16.32 0.192 ;
     RECT  16.344 0.144 16.464 0.192 ;
     RECT  16.488 0.144 16.608 0.192 ;
     RECT  16.632 0.144 16.752 0.192 ;
     RECT  16.776 0.144 16.944 0.192 ;
     RECT  16.968 0.144 17.088 0.192 ;
     RECT  17.112 0.144 17.232 0.192 ;
     RECT  17.256 0.144 17.376 0.192 ;
     RECT  17.4 0.144 17.568 0.192 ;
     RECT  17.592 0.144 17.712 0.192 ;
     RECT  17.736 0.144 17.856 0.192 ;
     RECT  17.88 0.144 18 0.192 ;
     RECT  18.024 0.144 18.192 0.192 ;
     RECT  18.216 0.144 18.336 0.192 ;
     RECT  18.36 0.144 18.48 0.192 ;
     RECT  18.504 0.144 18.624 0.192 ;
     RECT  18.648 0.144 18.816 0.192 ;
     RECT  18.84 0.144 18.96 0.192 ;
     RECT  18.984 0.144 19.104 0.192 ;
     RECT  19.128 0.144 19.248 0.192 ;
     RECT  19.272 0.144 19.44 0.192 ;
     RECT  19.464 0.144 19.584 0.192 ;
     RECT  19.608 0.144 19.728 0.192 ;
     RECT  19.752 0.144 19.872 0.192 ;
     RECT  19.896 0.144 20.064 0.192 ;
     RECT  20.088 0.144 20.208 0.192 ;
     RECT  20.232 0.144 20.352 0.192 ;
     RECT  20.376 0.144 20.496 0.192 ;
     RECT  20.52 0.144 20.688 0.192 ;
     RECT  20.712 0.144 20.832 0.192 ;
     RECT  20.856 0.144 20.976 0.192 ;
     RECT  21 0.144 21.12 0.192 ;
     RECT  21.144 0.144 21.312 0.192 ;
     RECT  21.336 0.144 21.456 0.192 ;
     RECT  21.48 0.144 21.6 0.192 ;
     RECT  21.624 0.144 21.744 0.192 ;
     RECT  21.768 0.144 21.936 0.192 ;
     RECT  21.96 0.144 22.08 0.192 ;
     RECT  22.104 0.144 22.224 0.192 ;
     RECT  22.248 0.144 22.368 0.192 ;
     RECT  22.392 0.144 22.56 0.192 ;
     RECT  22.584 0.144 22.704 0.192 ;
     RECT  22.728 0.144 22.848 0.192 ;
     RECT  22.872 0.144 22.992 0.192 ;
     RECT  23.016 0.144 23.184 0.192 ;
     RECT  23.208 0.144 23.328 0.192 ;
     RECT  23.352 0.144 23.472 0.192 ;
     RECT  23.496 0.144 23.616 0.192 ;
     RECT  2.256 0.192 23.64 1.763 ;
     RECT  2.256 1.763 17.208 1.859 ;
     RECT  2.256 1.859 8.664 2.053 ;
     RECT  18.48 1.763 23.64 2.053 ;
     RECT  18.48 2.053 24.264 2.099 ;
     RECT  1.44 2.053 8.664 2.195 ;
     RECT  1.44 2.195 8.568 2.245 ;
     RECT  10.08 1.859 17.208 2.291 ;
     RECT  18.6 2.099 24.264 2.725 ;
     RECT  10.128 2.291 16.968 2.915 ;
     RECT  14.88 2.915 16.968 3.011 ;
     RECT  18.6 2.725 24.312 3.013 ;
     RECT  15.216 3.011 16.968 3.059 ;
     RECT  18.6 3.013 24.6 3.061 ;
     RECT  18.6 3.061 24.696 3.301 ;
     RECT  10.128 2.915 13.608 3.443 ;
     RECT  18.6 3.301 24.84 3.491 ;
     RECT  10.128 3.443 13.512 4.019 ;
     RECT  10.32 4.019 13.512 5.077 ;
     RECT  18.6 3.491 19.944 5.269 ;
     RECT  21.3 3.491 24.84 5.269 ;
     RECT  9.936 5.077 13.512 5.747 ;
     RECT  18.6 5.269 24.84 6.325 ;
     RECT  15.36 3.059 16.968 6.661 ;
     RECT  12.24 5.747 13.512 6.805 ;
     RECT  15.36 6.661 17.16 6.853 ;
     RECT  18.24 6.325 24.84 6.853 ;
     RECT  0.528 2.245 8.568 6.899 ;
     RECT  15.36 6.853 24.84 7.189 ;
     RECT  9.936 5.747 10.812 7.381 ;
     RECT  11.904 6.805 13.512 7.381 ;
     RECT  14.736 7.189 24.84 7.381 ;
     RECT  9.936 7.381 24.84 7.429 ;
     RECT  4.704 6.899 8.568 7.957 ;
     RECT  9.648 7.429 24.84 7.957 ;
     RECT  0.528 6.899 3.72 8.821 ;
     RECT  0.48 8.821 3.72 9.061 ;
     RECT  4.704 7.957 24.84 9.061 ;
     RECT  0.48 9.061 24.84 12.851 ;
     RECT  0.48 12.851 24.792 13.187 ;
     RECT  0.48 13.187 24.744 14.195 ;
     RECT  0.768 14.195 24.744 15.011 ;
     RECT  0.768 15.011 24.648 15.059 ;
     RECT  0.816 15.059 24.648 15.251 ;
     RECT  0.864 15.251 24.648 15.299 ;
     RECT  0.864 15.299 0.888 15.347 ;
     RECT  2.256 15.299 24.648 16.067 ;
     RECT  2.256 16.067 24.552 16.643 ;
     RECT  2.256 16.643 23.736 17.088 ;
     RECT  2.28 17.088 2.4 17.104 ;
     RECT  2.424 17.088 2.592 17.104 ;
     RECT  2.616 17.088 2.736 17.104 ;
     RECT  2.76 17.088 2.88 17.104 ;
     RECT  2.904 17.088 3.072 17.104 ;
     RECT  3.096 17.088 3.216 17.104 ;
     RECT  3.24 17.088 3.36 17.104 ;
     RECT  3.384 17.088 3.504 17.104 ;
     RECT  3.528 17.088 3.696 17.104 ;
     RECT  3.72 17.088 3.84 17.104 ;
     RECT  3.864 17.088 3.984 17.104 ;
     RECT  4.008 17.088 4.128 17.104 ;
     RECT  4.152 17.088 4.32 17.104 ;
     RECT  4.344 17.088 4.464 17.104 ;
     RECT  4.488 17.088 4.608 17.104 ;
     RECT  4.632 17.088 4.752 17.104 ;
     RECT  4.776 17.088 4.944 17.104 ;
     RECT  4.968 17.088 5.088 17.104 ;
     RECT  5.112 17.088 5.232 17.104 ;
     RECT  5.256 17.088 5.376 17.104 ;
     RECT  5.4 17.088 5.568 17.104 ;
     RECT  5.592 17.088 5.712 17.104 ;
     RECT  5.736 17.088 5.856 17.104 ;
     RECT  5.88 17.088 6 17.104 ;
     RECT  6.024 17.088 6.192 17.104 ;
     RECT  6.216 17.088 6.336 17.104 ;
     RECT  6.36 17.088 6.48 17.104 ;
     RECT  6.504 17.088 6.624 17.104 ;
     RECT  6.648 17.088 6.816 17.104 ;
     RECT  6.84 17.088 6.96 17.104 ;
     RECT  6.984 17.088 7.104 17.104 ;
     RECT  7.128 17.088 7.296 17.104 ;
     RECT  7.32 17.088 7.44 17.104 ;
     RECT  7.464 17.088 7.584 17.104 ;
     RECT  7.608 17.088 7.728 17.104 ;
     RECT  7.752 17.088 7.92 17.104 ;
     RECT  7.944 17.088 8.064 17.104 ;
     RECT  8.088 17.088 8.208 17.104 ;
     RECT  8.232 17.088 8.352 17.104 ;
     RECT  8.376 17.088 8.544 17.104 ;
     RECT  8.568 17.088 8.688 17.104 ;
     RECT  8.712 17.088 8.832 17.104 ;
     RECT  8.856 17.088 8.976 17.104 ;
     RECT  9 17.088 9.168 17.104 ;
     RECT  9.192 17.088 9.312 17.104 ;
     RECT  9.336 17.088 9.456 17.104 ;
     RECT  9.48 17.088 9.6 17.104 ;
     RECT  9.624 17.088 9.792 17.104 ;
     RECT  9.816 17.088 9.936 17.104 ;
     RECT  9.96 17.088 10.08 17.104 ;
     RECT  10.104 17.088 10.272 17.104 ;
     RECT  10.296 17.088 10.416 17.104 ;
     RECT  10.44 17.088 10.56 17.104 ;
     RECT  10.584 17.088 10.704 17.104 ;
     RECT  10.728 17.088 10.896 17.104 ;
     RECT  10.92 17.088 11.04 17.104 ;
     RECT  11.064 17.088 11.184 17.104 ;
     RECT  11.208 17.088 11.328 17.104 ;
     RECT  11.352 17.088 11.52 17.104 ;
     RECT  11.544 17.088 11.664 17.104 ;
     RECT  11.688 17.088 11.808 17.104 ;
     RECT  11.832 17.088 11.952 17.104 ;
     RECT  11.976 17.088 12.144 17.104 ;
     RECT  12.168 17.088 12.288 17.104 ;
     RECT  12.312 17.088 12.432 17.104 ;
     RECT  12.456 17.088 12.576 17.104 ;
     RECT  12.6 17.088 12.768 17.104 ;
     RECT  12.792 17.088 12.912 17.104 ;
     RECT  12.936 17.088 13.056 17.104 ;
     RECT  13.08 17.088 13.2 17.104 ;
     RECT  13.224 17.088 13.392 17.104 ;
     RECT  13.416 17.088 13.536 17.104 ;
     RECT  13.56 17.088 13.68 17.104 ;
     RECT  13.704 17.088 13.824 17.104 ;
     RECT  13.848 17.088 14.016 17.104 ;
     RECT  14.04 17.088 14.16 17.104 ;
     RECT  14.184 17.088 14.304 17.104 ;
     RECT  14.328 17.088 14.496 17.104 ;
     RECT  14.52 17.088 14.64 17.104 ;
     RECT  14.664 17.088 14.784 17.104 ;
     RECT  14.808 17.088 14.928 17.104 ;
     RECT  14.952 17.088 15.12 17.104 ;
     RECT  15.144 17.088 15.264 17.104 ;
     RECT  15.288 17.088 15.408 17.104 ;
     RECT  15.432 17.088 15.552 17.104 ;
     RECT  15.576 17.088 15.744 17.104 ;
     RECT  15.768 17.088 15.888 17.104 ;
     RECT  15.912 17.088 16.032 17.104 ;
     RECT  16.056 17.088 16.176 17.104 ;
     RECT  16.2 17.088 16.368 17.104 ;
     RECT  16.392 17.088 16.512 17.104 ;
     RECT  16.536 17.088 16.656 17.104 ;
     RECT  16.68 17.088 16.8 17.104 ;
     RECT  16.824 17.088 16.992 17.104 ;
     RECT  17.016 17.088 17.136 17.104 ;
     RECT  17.16 17.088 17.28 17.104 ;
     RECT  17.304 17.088 17.472 17.104 ;
     RECT  17.496 17.088 17.616 17.104 ;
     RECT  17.64 17.088 17.76 17.104 ;
     RECT  17.784 17.088 17.904 17.104 ;
     RECT  17.928 17.088 18.096 17.104 ;
     RECT  18.12 17.088 18.24 17.104 ;
     RECT  18.264 17.088 18.384 17.104 ;
     RECT  18.408 17.088 18.528 17.104 ;
     RECT  18.552 17.088 18.72 17.104 ;
     RECT  18.744 17.088 18.864 17.104 ;
     RECT  18.888 17.088 19.008 17.104 ;
     RECT  19.032 17.088 19.152 17.104 ;
     RECT  19.176 17.088 19.344 17.104 ;
     RECT  19.368 17.088 19.488 17.104 ;
     RECT  19.512 17.088 19.632 17.104 ;
     RECT  19.656 17.088 19.776 17.104 ;
     RECT  19.8 17.088 19.968 17.104 ;
     RECT  19.992 17.088 20.112 17.104 ;
     RECT  20.136 17.088 20.256 17.104 ;
     RECT  20.28 17.088 20.4 17.104 ;
     RECT  20.424 17.088 20.592 17.104 ;
     RECT  20.616 17.088 20.736 17.104 ;
     RECT  20.76 17.088 20.88 17.104 ;
     RECT  20.904 17.088 21.072 17.104 ;
     RECT  21.096 17.088 21.216 17.104 ;
     RECT  21.24 17.088 21.36 17.104 ;
     RECT  21.384 17.088 21.504 17.104 ;
     RECT  21.528 17.088 21.696 17.104 ;
     RECT  21.72 17.088 21.84 17.104 ;
     RECT  21.864 17.088 21.984 17.104 ;
     RECT  22.008 17.088 22.128 17.104 ;
     RECT  22.152 17.088 22.32 17.104 ;
     RECT  22.344 17.088 22.464 17.104 ;
     RECT  22.488 17.088 22.608 17.104 ;
     RECT  22.632 17.088 22.752 17.104 ;
     RECT  22.776 17.088 22.944 17.104 ;
     RECT  22.968 17.088 23.088 17.104 ;
     RECT  23.112 17.088 23.232 17.104 ;
     RECT  23.256 17.088 23.376 17.104 ;
     RECT  23.4 17.088 23.568 17.104 ;
     RECT  23.592 17.088 23.712 17.104 ;
     RECT  17.208 1.763 18.48 2.099 ;
     RECT  8.664 1.859 10.08 2.195 ;
     RECT  17.208 2.099 18.6 2.291 ;
     RECT  8.568 2.195 10.08 2.291 ;
     RECT  13.608 2.915 14.88 3.011 ;
     RECT  19.944 3.491 21.3 5.269 ;
     RECT  10.128 4.019 10.32 5.077 ;
     RECT  8.568 5.077 9.936 7.429 ;
     RECT  10.812 5.747 12.24 6.805 ;
     RECT  16.968 6.325 18.24 6.661 ;
     RECT  17.16 6.661 18.24 6.853 ;
     RECT  10.812 6.805 11.904 7.381 ;
     RECT  3.72 6.899 4.704 9.061 ;
     RECT  13.512 7.189 14.736 7.381 ;
     RECT  8.568 7.429 9.648 7.957 ;
     RECT  0.888 15.299 2.256 15.347 ;
  END
END dsfd_dvrlyh_276_NS
END LIBRARY
